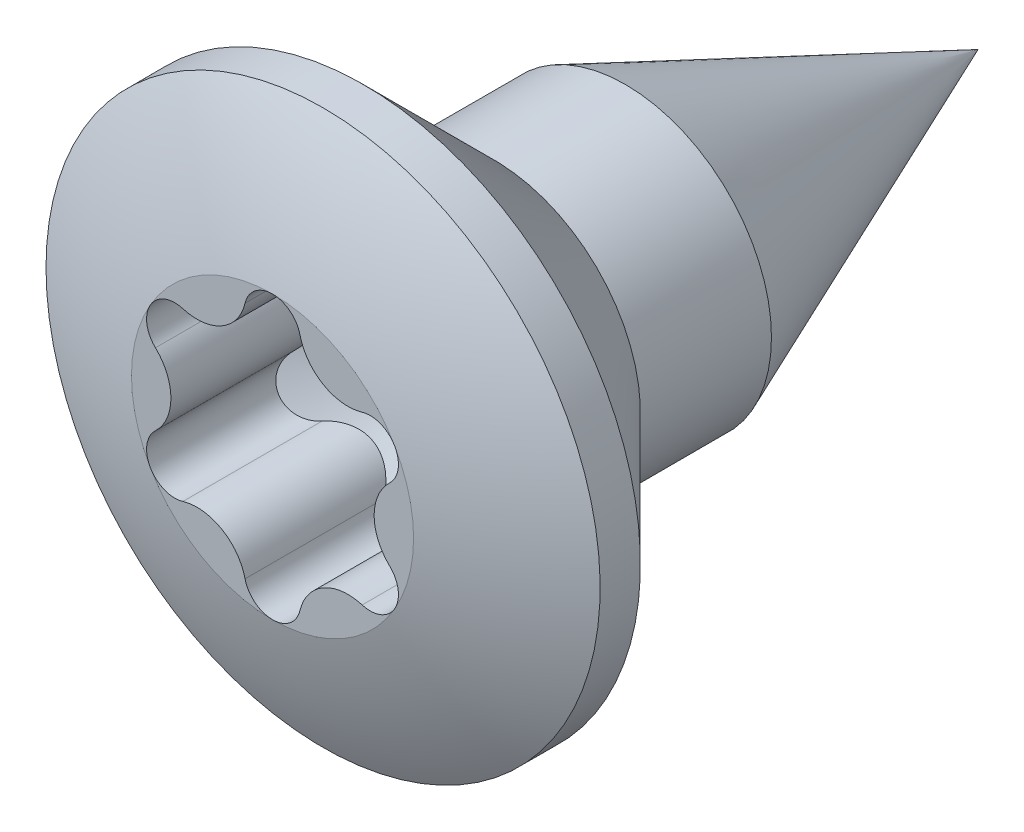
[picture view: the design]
ISO-10303-21;
HEADER;
FILE_DESCRIPTION(('STEP AP214'),'2;1');
FILE_NAME('part.step','',(''),(''),'','','');
FILE_SCHEMA(('AUTOMOTIVE_DESIGN { 1 0 10303 214 1 1 1 1 }'));
ENDSEC;
DATA;
#1=APPLICATION_CONTEXT('core data for automotive mechanical design processes');
#2=APPLICATION_PROTOCOL_DEFINITION('international standard','automotive_design',2000,#1);
#3=PRODUCT_CONTEXT('',#1,'mechanical');
#4=PRODUCT('Part','Part','',(#3));
#5=PRODUCT_RELATED_PRODUCT_CATEGORY('part','',(#4));
#6=PRODUCT_DEFINITION_FORMATION('','',#4);
#7=PRODUCT_DEFINITION_CONTEXT('part definition',#1,'design');
#8=PRODUCT_DEFINITION('design','',#6,#7);
#9=PRODUCT_DEFINITION_SHAPE('','',#8);
#10=(LENGTH_UNIT() NAMED_UNIT(*) SI_UNIT(.MILLI.,.METRE.));
#11=(NAMED_UNIT(*) PLANE_ANGLE_UNIT() SI_UNIT($,.RADIAN.));
#12=(NAMED_UNIT(*) SI_UNIT($,.STERADIAN.) SOLID_ANGLE_UNIT());
#13=UNCERTAINTY_MEASURE_WITH_UNIT(LENGTH_MEASURE(1.E-05),#10,'distance_accuracy_value','');
#14=(GEOMETRIC_REPRESENTATION_CONTEXT(3) GLOBAL_UNCERTAINTY_ASSIGNED_CONTEXT((#13)) GLOBAL_UNIT_ASSIGNED_CONTEXT((#10,
#11,#12)) REPRESENTATION_CONTEXT('',''));
#15=CARTESIAN_POINT('',(0.,0.,0.));
#16=DIRECTION('',(0.,0.,1.));
#17=DIRECTION('',(1.,0.,0.));
#18=AXIS2_PLACEMENT_3D('',#15,#16,#17);
#19=CARTESIAN_POINT('',(0.,0.,-2.1112048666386));
#20=DIRECTION('',(0.,0.,1.));
#21=DIRECTION('',(1.,0.,0.));
#22=AXIS2_PLACEMENT_3D('',#19,#20,#21);
#23=CONICAL_SURFACE('',#22,0.,1.02974425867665);
#24=CARTESIAN_POINT('',(0.,0.,-2.1112048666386));
#25=VERTEX_POINT('',#24);
#26=VERTEX_LOOP('',#25);
#27=FACE_BOUND('',#26,.T.);
#28=CARTESIAN_POINT('',(-0.889482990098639,0.828188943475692,-1.3809485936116));
#29=CARTESIAN_POINT('',(-0.905012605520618,0.832859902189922,-1.37220465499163));
#30=CARTESIAN_POINT('',(-0.921115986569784,0.836208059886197,-1.36371635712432));
#31=CARTESIAN_POINT('',(-0.954086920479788,0.840042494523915,-1.34741223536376));
#32=CARTESIAN_POINT('',(-0.970957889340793,0.840514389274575,-1.33959998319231));
#33=CARTESIAN_POINT('',(-1.00497300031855,0.838325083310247,-1.32487597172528));
#34=CARTESIAN_POINT('',(-1.02211786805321,0.835653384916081,-1.31796731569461));
#35=CARTESIAN_POINT('',(-1.05598176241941,0.827025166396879,-1.30531782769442));
#36=CARTESIAN_POINT('',(-1.07270160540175,0.821075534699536,-1.29957458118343));
#37=CARTESIAN_POINT('',(-1.1034719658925,0.806641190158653,-1.28995390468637));
#38=CARTESIAN_POINT('',(-1.11762414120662,0.798458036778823,-1.28594959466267));
#39=CARTESIAN_POINT('',(-1.14447104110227,0.779568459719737,-1.27921267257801));
#40=CARTESIAN_POINT('',(-1.15716729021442,0.768864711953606,-1.27647872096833));
#41=CARTESIAN_POINT('',(-1.17729540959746,0.748550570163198,-1.27296356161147));
#42=CARTESIAN_POINT('',(-1.18520819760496,0.739467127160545,-1.27185045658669));
#43=CARTESIAN_POINT('',(-1.1998230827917,0.720320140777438,-1.2703663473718));
#44=CARTESIAN_POINT('',(-1.2065255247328,0.710256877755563,-1.26999513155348));
#45=CARTESIAN_POINT('',(-1.21977835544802,0.687257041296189,-1.2700059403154));
#46=CARTESIAN_POINT('',(-1.22603166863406,0.674147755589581,-1.27055300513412));
#47=CARTESIAN_POINT('',(-1.23641852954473,0.647192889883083,-1.27271175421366));
#48=CARTESIAN_POINT('',(-1.24055077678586,0.633346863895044,-1.27432409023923));
#49=CARTESIAN_POINT('',(-1.24663514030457,0.605290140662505,-1.2785670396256));
#50=CARTESIAN_POINT('',(-1.24858010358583,0.591078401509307,-1.28120095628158));
#51=CARTESIAN_POINT('',(-1.25029508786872,0.562733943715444,-1.28740498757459));
#52=CARTESIAN_POINT('',(-1.25006510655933,0.54860122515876,-1.29097510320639));
#53=CARTESIAN_POINT('',(-1.24749330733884,0.520272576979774,-1.29909536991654));
#54=CARTESIAN_POINT('',(-1.24507670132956,0.506092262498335,-1.30367585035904));
#55=CARTESIAN_POINT('',(-1.23820796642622,0.478520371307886,-1.31361880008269));
#56=CARTESIAN_POINT('',(-1.23375477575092,0.465129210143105,-1.31898167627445));
#57=CARTESIAN_POINT('',(-1.22253305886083,0.438209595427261,-1.33089763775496));
#58=CARTESIAN_POINT('',(-1.2155883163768,0.424783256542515,-1.33751495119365));
#59=CARTESIAN_POINT('',(-1.19983715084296,0.399459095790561,-1.35138645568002));
#60=CARTESIAN_POINT('',(-1.191031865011,0.387560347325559,-1.35864025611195));
#61=CARTESIAN_POINT('',(-1.17525254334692,0.36936940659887,-1.3709921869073));
#62=CARTESIAN_POINT('',(-1.16873097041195,0.36258186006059,-1.37594624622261));
#63=CARTESIAN_POINT('',(-1.1619260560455,0.356175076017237,-1.380984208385));
#64=B_SPLINE_CURVE_WITH_KNOTS('',3,(#28,#29,#30,#31,#32,#33,#34,#35,#36,#37,#38,#39,#40,#41,#42,
#43,#44,#45,#46,#47,#48,#49,#50,#51,#52,#53,#54,#55,#56,#57,#58,#59,#60,#61,#62,#63),
.UNSPECIFIED.,.F.,.F.,(4,2,2,2,2,2,2,2,2,2,2,2,2,2,2,2,2,4),(0.,0.0552575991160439,
0.110791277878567,0.166510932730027,0.22211393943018,0.272328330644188,0.322489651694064,
0.358668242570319,0.394836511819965,0.438220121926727,0.481630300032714,0.525182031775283,
0.568733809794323,0.613833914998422,0.658957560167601,0.708259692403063,0.757531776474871,
0.789391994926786),.UNSPECIFIED.);
#65=CARTESIAN_POINT('',(-0.889682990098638,0.828248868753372,-1.38083610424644));
#66=VERTEX_POINT('',#65);
#67=CARTESIAN_POINT('',(-1.16212605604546,0.356363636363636,-1.38083610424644));
#68=VERTEX_POINT('',#67);
#69=EDGE_CURVE('E352',#66,#68,#64,.T.);
#70=ORIENTED_EDGE('',*,*,#69,.T.);
#71=CARTESIAN_POINT('',(-1.16232605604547,-0.356552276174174,-1.38068797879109));
#72=CARTESIAN_POINT('',(-1.14371471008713,-0.339008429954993,-1.3944473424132));
#73=CARTESIAN_POINT('',(-1.12623898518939,-0.319778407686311,-1.40780167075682));
#74=CARTESIAN_POINT('',(-1.0940425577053,-0.277971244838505,-1.43302652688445));
#75=CARTESIAN_POINT('',(-1.07934669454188,-0.25536688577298,-1.44488338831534));
#76=CARTESIAN_POINT('',(-1.05592099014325,-0.211603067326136,-1.46420788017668));
#77=CARTESIAN_POINT('',(-1.04659041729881,-0.19094971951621,-1.47208171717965));
#78=CARTESIAN_POINT('',(-1.03075231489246,-0.147964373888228,-1.48563194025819));
#79=CARTESIAN_POINT('',(-1.02423599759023,-0.125637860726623,-1.49131516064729));
#80=CARTESIAN_POINT('',(-1.01435941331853,-0.079551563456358,-1.49999377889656));
#81=CARTESIAN_POINT('',(-1.0110282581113,-0.0557806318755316,-1.50296437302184));
#82=CARTESIAN_POINT('',(-1.00791111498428,-0.007814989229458,-1.50574251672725));
#83=CARTESIAN_POINT('',(-1.00812457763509,0.0163796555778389,-1.50555055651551));
#84=CARTESIAN_POINT('',(-1.01181089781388,0.0610871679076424,-1.5022685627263));
#85=CARTESIAN_POINT('',(-1.01485301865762,0.0816670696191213,-1.49956155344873));
#86=CARTESIAN_POINT('',(-1.02339718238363,0.121903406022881,-1.49205082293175));
#87=CARTESIAN_POINT('',(-1.02889950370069,0.141559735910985,-1.48724686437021));
#88=CARTESIAN_POINT('',(-1.04242424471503,0.180555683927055,-1.4756266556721));
#89=CARTESIAN_POINT('',(-1.05056086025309,0.199828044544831,-1.46872028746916));
#90=CARTESIAN_POINT('',(-1.068925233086,0.236739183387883,-1.45343869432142));
#91=CARTESIAN_POINT('',(-1.0791555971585,0.254375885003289,-1.4450616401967));
#92=CARTESIAN_POINT('',(-1.1008414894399,0.287023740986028,-1.42768345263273));
#93=CARTESIAN_POINT('',(-1.1122089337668,0.302122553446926,-1.41873527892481));
#94=CARTESIAN_POINT('',(-1.13629839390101,0.330607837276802,-1.40016219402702));
#95=CARTESIAN_POINT('',(-1.14901444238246,0.344001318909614,-1.39054032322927));
#96=CARTESIAN_POINT('',(-1.16232605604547,0.356552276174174,-1.38068797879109));
#97=B_SPLINE_CURVE_WITH_KNOTS('',3,(#71,#72,#73,#74,#75,#76,#77,#78,#79,#80,#81,#82,#83,#84,#85,
#86,#87,#88,#89,#90,#91,#92,#93,#94,#95,#96),.UNSPECIFIED.,.F.,.F.,(4,2,2,2,2,2,2,2,2,2,2,2,4),
(0.,0.0872151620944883,0.175176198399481,0.246867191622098,0.318332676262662,0.390445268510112,
0.462546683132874,0.525200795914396,0.587862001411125,0.653718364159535,0.719657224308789,
0.782262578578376,0.844601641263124),.UNSPECIFIED.);
#98=CARTESIAN_POINT('',(-1.16212605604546,-0.356363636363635,-1.38083610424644));
#99=VERTEX_POINT('',#98);
#100=EDGE_CURVE('E272',#99,#68,#97,.T.);
#101=ORIENTED_EDGE('',*,*,#100,.F.);
#102=CARTESIAN_POINT('',(-1.16192605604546,-0.356175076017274,-1.38098420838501));
#103=CARTESIAN_POINT('',(-1.17373931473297,-0.367286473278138,-1.3722388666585));
#104=CARTESIAN_POINT('',(-1.18469402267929,-0.379556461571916,-1.36374908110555));
#105=CARTESIAN_POINT('',(-1.20450727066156,-0.406189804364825,-1.34744184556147));
#106=CARTESIAN_POINT('',(-1.21335506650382,-0.42056330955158,-1.33962796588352));
#107=CARTESIAN_POINT('',(-1.22847401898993,-0.451114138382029,-1.32490059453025));
#108=CARTESIAN_POINT('',(-1.23473645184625,-0.467297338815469,-1.31799020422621));
#109=CARTESIAN_POINT('',(-1.24420364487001,-0.500938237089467,-1.30533714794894));
#110=CARTESIAN_POINT('',(-1.24741476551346,-0.518393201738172,-1.2995920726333));
#111=CARTESIAN_POINT('',(-1.25030630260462,-0.552259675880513,-1.28996792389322));
#112=CARTESIAN_POINT('',(-1.25029873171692,-0.568608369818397,-1.28596196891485));
#113=CARTESIAN_POINT('',(-1.24736927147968,-0.601305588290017,-1.27922187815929));
#114=CARTESIAN_POINT('',(-1.2444505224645,-0.617654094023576,-1.27648637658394));
#115=CARTESIAN_POINT('',(-1.23694473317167,-0.645178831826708,-1.27297710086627));
#116=CARTESIAN_POINT('',(-1.23306322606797,-0.656509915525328,-1.27186728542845));
#117=CARTESIAN_POINT('',(-1.22386207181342,-0.678621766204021,-1.27038116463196));
#118=CARTESIAN_POINT('',(-1.21854281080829,-0.689402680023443,-1.27000466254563));
#119=CARTESIAN_POINT('',(-1.20528451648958,-0.712408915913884,-1.26999444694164));
#120=CARTESIAN_POINT('',(-1.19702890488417,-0.724453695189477,-1.27053576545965));
#121=CARTESIAN_POINT('',(-1.17880028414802,-0.747061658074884,-1.27269462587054));
#122=CARTESIAN_POINT('',(-1.16882619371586,-0.757623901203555,-1.27431284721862));
#123=CARTESIAN_POINT('',(-1.14751395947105,-0.776972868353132,-1.27856708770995));
#124=CARTESIAN_POINT('',(-1.13617862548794,-0.785763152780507,-1.28120103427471));
#125=CARTESIAN_POINT('',(-1.11248909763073,-0.801420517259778,-1.28740508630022));
#126=CARTESIAN_POINT('',(-1.10013492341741,-0.808287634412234,-1.29097517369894));
#127=CARTESIAN_POINT('',(-1.07431583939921,-0.820224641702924,-1.29909539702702));
#128=CARTESIAN_POINT('',(-1.06082705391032,-0.825221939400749,-1.30367586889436));
#129=CARTESIAN_POINT('',(-1.0335147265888,-0.833059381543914,-1.31361882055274));
#130=CARTESIAN_POINT('',(-1.01969101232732,-0.835898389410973,-1.3189817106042));
#131=CARTESIAN_POINT('',(-0.99076702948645,-0.839639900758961,-1.33089769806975));
#132=CARTESIAN_POINT('',(-0.975667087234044,-0.840338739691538,-1.337515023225));
#133=CARTESIAN_POINT('',(-0.94586012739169,-0.839359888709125,-1.35138653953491));
#134=CARTESIAN_POINT('',(-0.931152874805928,-0.837683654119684,-1.35864033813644));
#135=CARTESIAN_POINT('',(-0.907531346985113,-0.833118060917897,-1.37098080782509));
#136=CARTESIAN_POINT('',(-0.898413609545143,-0.830870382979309,-1.37592292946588));
#137=CARTESIAN_POINT('',(-0.889482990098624,-0.828188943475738,-1.38094859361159));
#138=B_SPLINE_CURVE_WITH_KNOTS('',3,(#102,#103,#104,#105,#106,#107,#108,#109,#110,#111,#112,
#113,#114,#115,#116,#117,#118,#119,#120,#121,#122,#123,#124,#125,#126,#127,#128,#129,#130,#131,
#132,#133,#134,#135,#136,#137),.UNSPECIFIED.,.F.,.F.,(4,2,2,2,2,2,2,2,2,2,2,2,2,2,2,2,2,4),(0.,
0.055261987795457,0.110800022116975,0.166523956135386,0.222131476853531,0.272349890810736,
0.322514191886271,0.358487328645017,0.394450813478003,0.438064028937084,0.481704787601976,
0.525256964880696,0.568808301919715,0.613908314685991,0.659032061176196,0.708334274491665,
0.757606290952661,0.789391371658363),.UNSPECIFIED.);
#139=CARTESIAN_POINT('',(-0.889682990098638,-0.828248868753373,-1.38083610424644));
#140=VERTEX_POINT('',#139);
#141=EDGE_CURVE('E252',#99,#140,#138,.T.);
#142=ORIENTED_EDGE('',*,*,#141,.T.);
#143=CARTESIAN_POINT('',(-0.27239567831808,-1.18481250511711,-1.38072536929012));
#144=CARTESIAN_POINT('',(-0.278286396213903,-1.15992581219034,-1.39448233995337));
#145=CARTESIAN_POINT('',(-0.286204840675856,-1.13517966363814,-1.4078341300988));
#146=CARTESIAN_POINT('',(-0.306317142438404,-1.08640000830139,-1.43305368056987));
#147=CARTESIAN_POINT('',(-0.318546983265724,-1.0623744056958,-1.44490777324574));
#148=CARTESIAN_POINT('',(-0.344737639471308,-1.02021115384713,-1.46422746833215));
#149=CARTESIAN_POINT('',(-0.357960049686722,-1.00180632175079,-1.47209923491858));
#150=CARTESIAN_POINT('',(-0.387269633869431,-0.966602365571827,-1.4856451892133));
#151=CARTESIAN_POINT('',(-0.403347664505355,-0.949798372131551,-1.49132621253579));
#152=CARTESIAN_POINT('',(-0.438322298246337,-0.918207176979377,-1.50000045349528));
#153=CARTESIAN_POINT('',(-0.457243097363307,-0.903439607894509,-1.50296887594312));
#154=CARTESIAN_POINT('',(-0.497223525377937,-0.876762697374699,-1.50574304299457));
#155=CARTESIAN_POINT('',(-0.518282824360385,-0.864852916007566,-1.50554927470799));
#156=CARTESIAN_POINT('',(-0.558843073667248,-0.845695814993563,-1.5022643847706));
#157=CARTESIAN_POINT('',(-0.578186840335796,-0.838042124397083,-1.49955608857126));
#158=CARTESIAN_POINT('',(-0.617304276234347,-0.825326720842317,-1.49204307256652));
#159=CARTESIAN_POINT('',(-0.637077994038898,-0.820265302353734,-1.48723811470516));
#160=CARTESIAN_POINT('',(-0.677612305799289,-0.81248293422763,-1.47561577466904));
#161=CARTESIAN_POINT('',(-0.698371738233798,-0.80989468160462,-1.46870816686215));
#162=CARTESIAN_POINT('',(-0.739521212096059,-0.807346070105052,-1.45342422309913));
#163=CARTESIAN_POINT('',(-0.759910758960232,-0.807389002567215,-1.44504606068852));
#164=CARTESIAN_POINT('',(-0.799009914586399,-0.809847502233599,-1.42767405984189));
#165=CARTESIAN_POINT('',(-0.817751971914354,-0.812140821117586,-1.41873411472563));
#166=CARTESIAN_POINT('',(-0.854431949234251,-0.818752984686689,-1.40017869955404));
#167=CARTESIAN_POINT('',(-0.872372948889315,-0.823063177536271,-1.39056626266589));
#168=CARTESIAN_POINT('',(-0.889882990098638,-0.828308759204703,-1.38072362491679));
#169=B_SPLINE_CURVE_WITH_KNOTS('',3,(#143,#144,#145,#146,#147,#148,#149,#150,#151,#152,#153,
#154,#155,#156,#157,#158,#159,#160,#161,#162,#163,#164,#165,#166,#167,#168),.UNSPECIFIED.,.F.,
.F.,(4,2,2,2,2,2,2,2,2,2,2,2,4),(0.,0.087205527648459,0.175156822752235,0.246842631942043,
0.318302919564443,0.39041005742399,0.462506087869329,0.525158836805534,0.587818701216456,
0.653677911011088,0.719619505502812,0.782166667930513,0.844447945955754),.UNSPECIFIED.);
#170=CARTESIAN_POINT('',(-0.27244306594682,-1.18461250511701,-1.38083610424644));
#171=VERTEX_POINT('',#170);
#172=EDGE_CURVE('E412',#171,#140,#169,.T.);
#173=ORIENTED_EDGE('',*,*,#172,.F.);
#174=CARTESIAN_POINT('',(-0.272490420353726,-1.18441250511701,-1.38094683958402));
#175=CARTESIAN_POINT('',(-0.268770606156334,-1.20019695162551,-1.37220296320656));
#176=CARTESIAN_POINT('',(-0.263618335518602,-1.21581687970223,-1.36371473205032));
#177=CARTESIAN_POINT('',(-0.250453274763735,-1.24628753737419,-1.34741076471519));
#178=CARTESIAN_POINT('',(-0.242426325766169,-1.26113403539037,-1.33959859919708));
#179=CARTESIAN_POINT('',(-0.223522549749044,-1.28949701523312,-1.32487477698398));
#180=CARTESIAN_POINT('',(-0.212636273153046,-1.30300887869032,-1.31796622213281));
#181=CARTESIAN_POINT('',(-0.188231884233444,-1.32802145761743,-1.30531690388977));
#182=CARTESIAN_POINT('',(-0.174719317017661,-1.33952631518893,-1.29957373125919));
#183=CARTESIAN_POINT('',(-0.146833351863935,-1.35895685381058,-1.28995316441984));
#184=CARTESIAN_POINT('',(-0.132670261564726,-1.36712133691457,-1.28594889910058));
#185=CARTESIAN_POINT('',(-0.102887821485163,-1.38092629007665,-1.27921215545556));
#186=CARTESIAN_POINT('',(-0.087270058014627,-1.38656947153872,-1.27647831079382));
#187=CARTESIAN_POINT('',(-0.059683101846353,-1.39382529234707,-1.27297212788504));
#188=CARTESIAN_POINT('',(-0.0479324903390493,-1.39612666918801,-1.27186360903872));
#189=CARTESIAN_POINT('',(-0.0241892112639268,-1.39920967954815,-1.27037965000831));
#190=CARTESIAN_POINT('',(-0.0121966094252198,-1.39999172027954,-1.27000401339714));
#191=CARTESIAN_POINT('',(0.0143530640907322,-1.4000098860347,-1.26999520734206));
#192=CARTESIAN_POINT('',(0.0289120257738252,-1.39888106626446,-1.2705373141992));
#193=CARTESIAN_POINT('',(0.0576052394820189,-1.39439532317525,-1.27269775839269));
#194=CARTESIAN_POINT('',(0.071739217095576,-1.39103699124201,-1.27431677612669));
#195=CARTESIAN_POINT('',(0.0991512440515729,-1.38225134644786,-1.27857258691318));
#196=CARTESIAN_POINT('',(0.112430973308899,-1.37682824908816,-1.28120730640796));
#197=CARTESIAN_POINT('',(0.137834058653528,-1.36413823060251,-1.28741286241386));
#198=CARTESIAN_POINT('',(0.149957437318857,-1.3568713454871,-1.29098368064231));
#199=CARTESIAN_POINT('',(0.173203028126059,-1.34047705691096,-1.29910538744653));
#200=CARTESIAN_POINT('',(0.184274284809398,-1.33129266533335,-1.30368662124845));
#201=CARTESIAN_POINT('',(0.204715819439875,-1.31155556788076,-1.31363105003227));
#202=CARTESIAN_POINT('',(0.214085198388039,-1.30100214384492,-1.31899465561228));
#203=CARTESIAN_POINT('',(0.231784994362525,-1.27782146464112,-1.33091215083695));
#204=CARTESIAN_POINT('',(0.239938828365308,-1.2650926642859,-1.33753027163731));
#205=CARTESIAN_POINT('',(0.253991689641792,-1.23878731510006,-1.3514033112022));
#206=CARTESIAN_POINT('',(0.259892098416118,-1.22521129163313,-1.35865783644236));
#207=CARTESIAN_POINT('',(0.267741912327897,-1.20248267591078,-1.37099262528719));
#208=CARTESIAN_POINT('',(0.27035012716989,-1.19347493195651,-1.37592807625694));
#209=CARTESIAN_POINT('',(0.272490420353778,-1.18441250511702,-1.38094683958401));
#210=B_SPLINE_CURVE_WITH_KNOTS('',3,(#174,#175,#176,#177,#178,#179,#180,#181,#182,#183,#184,
#185,#186,#187,#188,#189,#190,#191,#192,#193,#194,#195,#196,#197,#198,#199,#200,#201,#202,#203,
#204,#205,#206,#207,#208,#209),.UNSPECIFIED.,.F.,.F.,(4,2,2,2,2,2,2,2,2,2,2,2,2,2,2,2,2,4),(0.,
0.0552574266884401,0.110790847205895,0.166510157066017,0.222113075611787,0.272327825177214,
0.322488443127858,0.358450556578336,0.394403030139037,0.43801690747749,0.481658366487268,
0.525211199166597,0.568763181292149,0.613864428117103,0.658989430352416,0.708293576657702,
0.757567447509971,0.78930904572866),.UNSPECIFIED.);
#211=CARTESIAN_POINT('',(0.272443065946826,-1.18461250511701,-1.38083610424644));
#212=VERTEX_POINT('',#211);
#213=EDGE_CURVE('E448',#171,#212,#210,.T.);
#214=ORIENTED_EDGE('',*,*,#213,.T.);
#215=CARTESIAN_POINT('',(0.889882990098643,-0.828308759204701,-1.38072362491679));
#216=CARTESIAN_POINT('',(0.865385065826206,-0.820966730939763,-1.39448070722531));
#217=CARTESIAN_POINT('',(0.839994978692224,-0.815451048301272,-1.4078326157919));
#218=CARTESIAN_POINT('',(0.787694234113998,-0.808478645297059,-1.43305241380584));
#219=CARTESIAN_POINT('',(0.760772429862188,-0.807057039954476,-1.44490663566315));
#220=CARTESIAN_POINT('',(0.711162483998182,-0.808656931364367,-1.46422655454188));
#221=CARTESIAN_POINT('',(0.68861216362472,-0.810905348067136,-1.4720984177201));
#222=CARTESIAN_POINT('',(0.643469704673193,-0.81868600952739,-1.48564457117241));
#223=CARTESIAN_POINT('',(0.620877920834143,-0.82420790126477,-1.49132569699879));
#224=CARTESIAN_POINT('',(0.576031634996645,-0.838701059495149,-1.50000014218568));
#225=CARTESIAN_POINT('',(0.553782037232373,-0.847703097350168,-1.50296866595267));
#226=CARTESIAN_POINT('',(0.510688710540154,-0.868988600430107,-1.50574301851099));
#227=CARTESIAN_POINT('',(0.489844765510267,-0.881271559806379,-1.50554933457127));
#228=CARTESIAN_POINT('',(0.452973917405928,-0.906819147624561,-1.50226457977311));
#229=CARTESIAN_POINT('',(0.436673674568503,-0.919744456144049,-1.49955634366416));
#230=CARTESIAN_POINT('',(0.406102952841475,-0.947263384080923,-1.49204343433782));
#231=CARTESIAN_POINT('',(0.391832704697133,-0.961857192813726,-1.48723852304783));
#232=CARTESIAN_POINT('',(0.364825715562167,-0.993069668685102,-1.47561628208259));
#233=CARTESIAN_POINT('',(0.35220446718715,-1.00975367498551,-1.46870873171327));
#234=CARTESIAN_POINT('',(0.329422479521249,-1.04411573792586,-1.45342489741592));
#235=CARTESIAN_POINT('',(0.319264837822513,-1.06179501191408,-1.44504678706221));
#236=CARTESIAN_POINT('',(0.301844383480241,-1.09688480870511,-1.4276749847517));
#237=CARTESIAN_POINT('',(0.294459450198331,-1.11426230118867,-1.41873519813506));
#238=CARTESIAN_POINT('',(0.28184575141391,-1.14933364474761,-1.40018010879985));
#239=CARTESIAN_POINT('',(0.276607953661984,-1.16702583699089,-1.39056783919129));
#240=CARTESIAN_POINT('',(0.272395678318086,-1.18481250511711,-1.38072536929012));
#241=B_SPLINE_CURVE_WITH_KNOTS('',3,(#215,#216,#217,#218,#219,#220,#221,#222,#223,#224,#225,
#226,#227,#228,#229,#230,#231,#232,#233,#234,#235,#236,#237,#238,#239,#240),.UNSPECIFIED.,.F.,
.F.,(4,2,2,2,2,2,2,2,2,2,2,2,4),(0.,0.0872059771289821,0.175157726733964,0.246843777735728,
0.318304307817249,0.390411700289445,0.462507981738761,0.525160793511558,0.587820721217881,
0.653679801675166,0.719621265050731,0.782167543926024,0.844447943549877),.UNSPECIFIED.);
#242=CARTESIAN_POINT('',(0.889682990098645,-0.828248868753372,-1.38083610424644));
#243=VERTEX_POINT('',#242);
#244=EDGE_CURVE('E458',#243,#212,#241,.T.);
#245=ORIENTED_EDGE('',*,*,#244,.F.);
#246=CARTESIAN_POINT('',(0.889482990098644,-0.828188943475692,-1.3809485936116));
#247=CARTESIAN_POINT('',(0.905012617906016,-0.832859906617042,-1.3722046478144));
#248=CARTESIAN_POINT('',(0.9211160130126,-0.836208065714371,-1.36371634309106));
#249=CARTESIAN_POINT('',(0.954086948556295,-0.840042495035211,-1.34741222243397));
#250=CARTESIAN_POINT('',(0.97095790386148,-0.840514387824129,-1.33959997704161));
#251=CARTESIAN_POINT('',(1.00497295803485,-0.838325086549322,-1.32487598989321));
#252=CARTESIAN_POINT('',(1.02211778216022,-0.835653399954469,-1.3179673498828));
#253=CARTESIAN_POINT('',(1.05598168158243,-0.827025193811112,-1.30531785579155));
#254=CARTESIAN_POINT('',(1.07270157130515,-0.821075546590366,-1.29957459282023));
#255=CARTESIAN_POINT('',(1.10347212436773,-0.806641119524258,-1.28995385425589));
#256=CARTESIAN_POINT('',(1.11762443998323,-0.798457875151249,-1.2859495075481));
#257=CARTESIAN_POINT('',(1.14447134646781,-0.779568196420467,-1.2792126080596));
#258=CARTESIAN_POINT('',(1.15716749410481,-0.768864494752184,-1.27647868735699));
#259=CARTESIAN_POINT('',(1.17724157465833,-0.748604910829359,-1.27297296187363));
#260=CARTESIAN_POINT('',(1.18510709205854,-0.739583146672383,-1.27186469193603));
#261=CARTESIAN_POINT('',(1.19964404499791,-0.720570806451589,-1.27038063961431));
#262=CARTESIAN_POINT('',(1.20631579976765,-0.710580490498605,-1.27000466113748));
#263=CARTESIAN_POINT('',(1.21960641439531,-0.687602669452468,-1.26999444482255));
#264=CARTESIAN_POINT('',(1.22590969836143,-0.674430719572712,-1.27053575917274));
#265=CARTESIAN_POINT('',(1.23637447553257,-0.647340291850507,-1.27269461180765));
#266=CARTESIAN_POINT('',(1.24053460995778,-0.633421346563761,-1.27431283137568));
#267=CARTESIAN_POINT('',(1.24663520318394,-0.60528991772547,-1.27856706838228));
#268=CARTESIAN_POINT('',(1.24858015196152,-0.591078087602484,-1.28120101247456));
#269=CARTESIAN_POINT('',(1.25029507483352,-0.5627336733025,-1.28740505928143));
#270=CARTESIAN_POINT('',(1.25006509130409,-0.54860108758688,-1.29097514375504));
#271=CARTESIAN_POINT('',(1.24749331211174,-0.520272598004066,-1.29909536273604));
#272=CARTESIAN_POINT('',(1.24507671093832,-0.506092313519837,-1.30367583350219));
#273=CARTESIAN_POINT('',(1.2382079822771,-0.478520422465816,-1.31361878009));
#274=CARTESIAN_POINT('',(1.23375478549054,-0.465129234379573,-1.31898166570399));
#275=CARTESIAN_POINT('',(1.22253305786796,-0.438209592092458,-1.33089763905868));
#276=CARTESIAN_POINT('',(1.21558831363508,-0.424783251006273,-1.33751495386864));
#277=CARTESIAN_POINT('',(1.19983714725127,-0.399459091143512,-1.35138645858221));
#278=CARTESIAN_POINT('',(1.191031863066,-0.387560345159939,-1.35864025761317));
#279=CARTESIAN_POINT('',(1.17525254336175,-0.369369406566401,-1.37099218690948));
#280=CARTESIAN_POINT('',(1.16873097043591,-0.362581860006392,-1.37594624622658));
#281=CARTESIAN_POINT('',(1.1619260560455,-0.356175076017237,-1.380984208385));
#282=B_SPLINE_CURVE_WITH_KNOTS('',3,(#246,#247,#248,#249,#250,#251,#252,#253,#254,#255,#256,
#257,#258,#259,#260,#261,#262,#263,#264,#265,#266,#267,#268,#269,#270,#271,#272,#273,#274,#275,
#276,#277,#278,#279,#280,#281),.UNSPECIFIED.,.F.,.F.,(4,2,2,2,2,2,2,2,2,2,2,2,2,2,2,2,2,4),(0.,
0.055257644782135,0.11079127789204,0.166510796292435,0.222113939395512,0.272328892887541,
0.322489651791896,0.358437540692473,0.394375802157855,0.437988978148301,0.481629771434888,
0.525181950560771,0.568733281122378,0.613833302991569,0.658957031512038,0.708259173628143,
0.757531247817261,0.789391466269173),.UNSPECIFIED.);
#283=CARTESIAN_POINT('',(1.16212605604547,-0.356363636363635,-1.38083610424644));
#284=VERTEX_POINT('',#283);
#285=EDGE_CURVE('E477',#243,#284,#282,.T.);
#286=ORIENTED_EDGE('',*,*,#285,.T.);
#287=CARTESIAN_POINT('',(1.16232605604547,0.356552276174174,-1.38068797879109));
#288=CARTESIAN_POINT('',(1.14371471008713,0.339008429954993,-1.3944473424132));
#289=CARTESIAN_POINT('',(1.1262389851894,0.319778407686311,-1.40780167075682));
#290=CARTESIAN_POINT('',(1.0940425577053,0.277971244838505,-1.43302652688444));
#291=CARTESIAN_POINT('',(1.07934669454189,0.25536688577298,-1.44488338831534));
#292=CARTESIAN_POINT('',(1.05592099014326,0.211603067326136,-1.46420788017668));
#293=CARTESIAN_POINT('',(1.04659041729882,0.19094971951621,-1.47208171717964));
#294=CARTESIAN_POINT('',(1.03075231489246,0.147964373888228,-1.48563194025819));
#295=CARTESIAN_POINT('',(1.02423599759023,0.125637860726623,-1.49131516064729));
#296=CARTESIAN_POINT('',(1.01435941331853,0.079551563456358,-1.49999377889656));
#297=CARTESIAN_POINT('',(1.01102825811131,0.0557806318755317,-1.50296437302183));
#298=CARTESIAN_POINT('',(1.00791111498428,0.0078149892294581,-1.50574251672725));
#299=CARTESIAN_POINT('',(1.00812457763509,-0.0163796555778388,-1.50555055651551));
#300=CARTESIAN_POINT('',(1.01181089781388,-0.0610871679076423,-1.50226856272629));
#301=CARTESIAN_POINT('',(1.01485301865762,-0.0816670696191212,-1.49956155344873));
#302=CARTESIAN_POINT('',(1.02339718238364,-0.121903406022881,-1.49205082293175));
#303=CARTESIAN_POINT('',(1.02889950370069,-0.141559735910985,-1.4872468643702));
#304=CARTESIAN_POINT('',(1.04242424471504,-0.180555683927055,-1.4756266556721));
#305=CARTESIAN_POINT('',(1.05056086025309,-0.199828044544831,-1.46872028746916));
#306=CARTESIAN_POINT('',(1.068925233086,-0.236739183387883,-1.45343869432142));
#307=CARTESIAN_POINT('',(1.0791555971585,-0.254375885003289,-1.4450616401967));
#308=CARTESIAN_POINT('',(1.1008414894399,-0.287023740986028,-1.42768345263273));
#309=CARTESIAN_POINT('',(1.1122089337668,-0.302122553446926,-1.41873527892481));
#310=CARTESIAN_POINT('',(1.13629839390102,-0.330607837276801,-1.40016219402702));
#311=CARTESIAN_POINT('',(1.14901444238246,-0.344001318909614,-1.39054032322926));
#312=CARTESIAN_POINT('',(1.16232605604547,-0.356552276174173,-1.38068797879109));
#313=B_SPLINE_CURVE_WITH_KNOTS('',3,(#287,#288,#289,#290,#291,#292,#293,#294,#295,#296,#297,
#298,#299,#300,#301,#302,#303,#304,#305,#306,#307,#308,#309,#310,#311,#312),.UNSPECIFIED.,.F.,
.F.,(4,2,2,2,2,2,2,2,2,2,2,2,4),(0.,0.087215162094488,0.175176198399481,0.246867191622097,
0.318332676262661,0.390445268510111,0.462546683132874,0.525200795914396,0.587862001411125,
0.653718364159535,0.719657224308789,0.782262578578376,0.844601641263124),.UNSPECIFIED.);
#314=CARTESIAN_POINT('',(1.16212605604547,0.35636363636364,-1.38083610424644));
#315=VERTEX_POINT('',#314);
#316=EDGE_CURVE('E488',#315,#284,#313,.T.);
#317=ORIENTED_EDGE('',*,*,#316,.F.);
#318=CARTESIAN_POINT('',(1.16192605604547,0.356175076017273,-1.38098420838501));
#319=CARTESIAN_POINT('',(1.17373931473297,0.367286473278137,-1.3722388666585));
#320=CARTESIAN_POINT('',(1.18469402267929,0.379556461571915,-1.36374908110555));
#321=CARTESIAN_POINT('',(1.20450727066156,0.406189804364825,-1.34744184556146));
#322=CARTESIAN_POINT('',(1.21335506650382,0.420563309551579,-1.33962796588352));
#323=CARTESIAN_POINT('',(1.22847401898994,0.451114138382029,-1.32490059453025));
#324=CARTESIAN_POINT('',(1.23473645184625,0.467297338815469,-1.31799020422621));
#325=CARTESIAN_POINT('',(1.24420364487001,0.500938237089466,-1.30533714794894));
#326=CARTESIAN_POINT('',(1.24741476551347,0.518393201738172,-1.2995920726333));
#327=CARTESIAN_POINT('',(1.25030630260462,0.552259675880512,-1.28996792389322));
#328=CARTESIAN_POINT('',(1.25029873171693,0.568608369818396,-1.28596196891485));
#329=CARTESIAN_POINT('',(1.24736927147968,0.601305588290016,-1.27922187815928));
#330=CARTESIAN_POINT('',(1.24445052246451,0.617654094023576,-1.27648637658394));
#331=CARTESIAN_POINT('',(1.23694473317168,0.645178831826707,-1.27297710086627));
#332=CARTESIAN_POINT('',(1.23306322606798,0.656509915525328,-1.27186728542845));
#333=CARTESIAN_POINT('',(1.22386207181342,0.678621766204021,-1.27038116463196));
#334=CARTESIAN_POINT('',(1.2185428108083,0.689402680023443,-1.27000466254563));
#335=CARTESIAN_POINT('',(1.20528451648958,0.712408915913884,-1.26999444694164));
#336=CARTESIAN_POINT('',(1.19702890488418,0.724453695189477,-1.27053576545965));
#337=CARTESIAN_POINT('',(1.17880028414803,0.747061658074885,-1.27269462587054));
#338=CARTESIAN_POINT('',(1.16882619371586,0.757623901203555,-1.27431284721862));
#339=CARTESIAN_POINT('',(1.14751395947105,0.776972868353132,-1.27856708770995));
#340=CARTESIAN_POINT('',(1.13617862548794,0.785763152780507,-1.28120103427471));
#341=CARTESIAN_POINT('',(1.11248909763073,0.801420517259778,-1.28740508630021));
#342=CARTESIAN_POINT('',(1.10013492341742,0.808287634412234,-1.29097517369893));
#343=CARTESIAN_POINT('',(1.07431583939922,0.820224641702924,-1.29909539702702));
#344=CARTESIAN_POINT('',(1.06082705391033,0.825221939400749,-1.30367586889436));
#345=CARTESIAN_POINT('',(1.0335147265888,0.833059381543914,-1.31361882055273));
#346=CARTESIAN_POINT('',(1.01969101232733,0.835898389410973,-1.3189817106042));
#347=CARTESIAN_POINT('',(0.990767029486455,0.839639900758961,-1.33089769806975));
#348=CARTESIAN_POINT('',(0.975667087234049,0.840338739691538,-1.337515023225));
#349=CARTESIAN_POINT('',(0.945860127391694,0.839359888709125,-1.35138653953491));
#350=CARTESIAN_POINT('',(0.931152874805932,0.837683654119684,-1.35864033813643));
#351=CARTESIAN_POINT('',(0.907531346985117,0.833118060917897,-1.37098080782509));
#352=CARTESIAN_POINT('',(0.898413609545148,0.830870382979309,-1.37592292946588));
#353=CARTESIAN_POINT('',(0.889482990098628,0.828188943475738,-1.38094859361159));
#354=B_SPLINE_CURVE_WITH_KNOTS('',3,(#318,#319,#320,#321,#322,#323,#324,#325,#326,#327,#328,
#329,#330,#331,#332,#333,#334,#335,#336,#337,#338,#339,#340,#341,#342,#343,#344,#345,#346,#347,
#348,#349,#350,#351,#352,#353),.UNSPECIFIED.,.F.,.F.,(4,2,2,2,2,2,2,2,2,2,2,2,2,2,2,2,2,4),(0.,
0.0552619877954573,0.110800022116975,0.166523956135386,0.222131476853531,0.272349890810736,
0.322514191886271,0.358487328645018,0.394450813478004,0.438064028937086,0.481704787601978,
0.525256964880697,0.568808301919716,0.613908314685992,0.659032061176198,0.708334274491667,
0.757606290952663,0.789391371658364),.UNSPECIFIED.);
#355=CARTESIAN_POINT('',(0.889682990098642,0.828248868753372,-1.38083610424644));
#356=VERTEX_POINT('',#355);
#357=EDGE_CURVE('E361',#315,#356,#354,.T.);
#358=ORIENTED_EDGE('',*,*,#357,.T.);
#359=CARTESIAN_POINT('',(0.272395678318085,1.18481250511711,-1.38072536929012));
#360=CARTESIAN_POINT('',(0.278286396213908,1.15992581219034,-1.39448233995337));
#361=CARTESIAN_POINT('',(0.286204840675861,1.13517966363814,-1.4078341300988));
#362=CARTESIAN_POINT('',(0.306317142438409,1.08640000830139,-1.43305368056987));
#363=CARTESIAN_POINT('',(0.318546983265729,1.0623744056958,-1.44490777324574));
#364=CARTESIAN_POINT('',(0.344737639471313,1.02021115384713,-1.46422746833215));
#365=CARTESIAN_POINT('',(0.357960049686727,1.00180632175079,-1.47209923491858));
#366=CARTESIAN_POINT('',(0.387269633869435,0.966602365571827,-1.4856451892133));
#367=CARTESIAN_POINT('',(0.40334766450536,0.949798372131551,-1.49132621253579));
#368=CARTESIAN_POINT('',(0.438322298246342,0.918207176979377,-1.50000045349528));
#369=CARTESIAN_POINT('',(0.457243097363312,0.903439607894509,-1.50296887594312));
#370=CARTESIAN_POINT('',(0.497223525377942,0.876762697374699,-1.50574304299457));
#371=CARTESIAN_POINT('',(0.51828282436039,0.864852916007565,-1.50554927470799));
#372=CARTESIAN_POINT('',(0.558843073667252,0.845695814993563,-1.50226438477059));
#373=CARTESIAN_POINT('',(0.578186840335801,0.838042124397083,-1.49955608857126));
#374=CARTESIAN_POINT('',(0.617304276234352,0.825326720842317,-1.49204307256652));
#375=CARTESIAN_POINT('',(0.637077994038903,0.820265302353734,-1.48723811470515));
#376=CARTESIAN_POINT('',(0.677612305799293,0.812482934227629,-1.47561577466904));
#377=CARTESIAN_POINT('',(0.698371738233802,0.80989468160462,-1.46870816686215));
#378=CARTESIAN_POINT('',(0.739521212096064,0.807346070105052,-1.45342422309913));
#379=CARTESIAN_POINT('',(0.759910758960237,0.807389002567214,-1.44504606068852));
#380=CARTESIAN_POINT('',(0.799009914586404,0.809847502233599,-1.42767405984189));
#381=CARTESIAN_POINT('',(0.817751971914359,0.812140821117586,-1.41873411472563));
#382=CARTESIAN_POINT('',(0.854431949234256,0.818752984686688,-1.40017869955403));
#383=CARTESIAN_POINT('',(0.872372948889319,0.82306317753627,-1.39056626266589));
#384=CARTESIAN_POINT('',(0.889882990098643,0.828308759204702,-1.38072362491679));
#385=B_SPLINE_CURVE_WITH_KNOTS('',3,(#359,#360,#361,#362,#363,#364,#365,#366,#367,#368,#369,
#370,#371,#372,#373,#374,#375,#376,#377,#378,#379,#380,#381,#382,#383,#384),.UNSPECIFIED.,.F.,
.F.,(4,2,2,2,2,2,2,2,2,2,2,2,4),(0.,0.0872055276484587,0.175156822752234,0.246842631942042,
0.318302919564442,0.39041005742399,0.462506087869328,0.525158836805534,0.587818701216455,
0.653677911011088,0.719619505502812,0.782166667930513,0.844447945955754),.UNSPECIFIED.);
#386=CARTESIAN_POINT('',(0.272443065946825,1.18461250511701,-1.38083610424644));
#387=VERTEX_POINT('',#386);
#388=EDGE_CURVE('E386',#387,#356,#385,.T.);
#389=ORIENTED_EDGE('',*,*,#388,.F.);
#390=CARTESIAN_POINT('',(0.272490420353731,1.18441250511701,-1.38094683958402));
#391=CARTESIAN_POINT('',(0.268770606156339,1.20019695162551,-1.37220296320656));
#392=CARTESIAN_POINT('',(0.263618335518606,1.21581687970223,-1.36371473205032));
#393=CARTESIAN_POINT('',(0.25045327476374,1.24628753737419,-1.34741076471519));
#394=CARTESIAN_POINT('',(0.242426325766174,1.26113403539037,-1.33959859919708));
#395=CARTESIAN_POINT('',(0.223522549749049,1.28949701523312,-1.32487477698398));
#396=CARTESIAN_POINT('',(0.212636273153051,1.30300887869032,-1.31796622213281));
#397=CARTESIAN_POINT('',(0.188231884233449,1.32802145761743,-1.30531690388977));
#398=CARTESIAN_POINT('',(0.174719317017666,1.33952631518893,-1.29957373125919));
#399=CARTESIAN_POINT('',(0.14683335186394,1.35895685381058,-1.28995316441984));
#400=CARTESIAN_POINT('',(0.132670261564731,1.36712133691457,-1.28594889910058));
#401=CARTESIAN_POINT('',(0.102887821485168,1.38092629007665,-1.27921215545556));
#402=CARTESIAN_POINT('',(0.0872700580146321,1.38656947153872,-1.27647831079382));
#403=CARTESIAN_POINT('',(0.0596831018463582,1.39382529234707,-1.27297212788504));
#404=CARTESIAN_POINT('',(0.0479324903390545,1.39612666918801,-1.27186360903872));
#405=CARTESIAN_POINT('',(0.0241892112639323,1.39920967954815,-1.27037965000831));
#406=CARTESIAN_POINT('',(0.0121966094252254,1.39999172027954,-1.27000401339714));
#407=CARTESIAN_POINT('',(-0.0143530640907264,1.4000098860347,-1.26999520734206));
#408=CARTESIAN_POINT('',(-0.0289120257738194,1.39888106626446,-1.2705373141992));
#409=CARTESIAN_POINT('',(-0.0576052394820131,1.39439532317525,-1.27269775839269));
#410=CARTESIAN_POINT('',(-0.0717392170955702,1.39103699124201,-1.27431677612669));
#411=CARTESIAN_POINT('',(-0.099151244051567,1.38225134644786,-1.27857258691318));
#412=CARTESIAN_POINT('',(-0.112430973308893,1.37682824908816,-1.28120730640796));
#413=CARTESIAN_POINT('',(-0.137834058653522,1.36413823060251,-1.28741286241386));
#414=CARTESIAN_POINT('',(-0.149957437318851,1.3568713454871,-1.29098368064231));
#415=CARTESIAN_POINT('',(-0.173203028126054,1.34047705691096,-1.29910538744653));
#416=CARTESIAN_POINT('',(-0.184274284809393,1.33129266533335,-1.30368662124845));
#417=CARTESIAN_POINT('',(-0.204715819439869,1.31155556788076,-1.31363105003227));
#418=CARTESIAN_POINT('',(-0.214085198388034,1.30100214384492,-1.31899465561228));
#419=CARTESIAN_POINT('',(-0.231784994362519,1.27782146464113,-1.33091215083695));
#420=CARTESIAN_POINT('',(-0.239938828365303,1.2650926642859,-1.33753027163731));
#421=CARTESIAN_POINT('',(-0.253991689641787,1.23878731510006,-1.3514033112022));
#422=CARTESIAN_POINT('',(-0.259892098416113,1.22521129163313,-1.35865783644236));
#423=CARTESIAN_POINT('',(-0.267741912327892,1.20248267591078,-1.37099262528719));
#424=CARTESIAN_POINT('',(-0.270350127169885,1.19347493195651,-1.37592807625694));
#425=CARTESIAN_POINT('',(-0.272490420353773,1.18441250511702,-1.38094683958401));
#426=B_SPLINE_CURVE_WITH_KNOTS('',3,(#390,#391,#392,#393,#394,#395,#396,#397,#398,#399,#400,
#401,#402,#403,#404,#405,#406,#407,#408,#409,#410,#411,#412,#413,#414,#415,#416,#417,#418,#419,
#420,#421,#422,#423,#424,#425),.UNSPECIFIED.,.F.,.F.,(4,2,2,2,2,2,2,2,2,2,2,2,2,2,2,2,2,4),(0.,
0.0552574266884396,0.110790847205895,0.166510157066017,0.222113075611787,0.272327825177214,
0.322488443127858,0.358450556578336,0.394403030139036,0.438016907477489,0.481658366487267,
0.525211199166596,0.568763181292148,0.613864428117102,0.658989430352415,0.7082935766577,
0.75756744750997,0.789309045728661),.UNSPECIFIED.);
#427=CARTESIAN_POINT('',(-0.272443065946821,1.18461250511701,-1.38083610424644));
#428=VERTEX_POINT('',#427);
#429=EDGE_CURVE('E346',#387,#428,#426,.T.);
#430=ORIENTED_EDGE('',*,*,#429,.T.);
#431=CARTESIAN_POINT('',(-0.889882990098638,0.828308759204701,-1.38072362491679));
#432=CARTESIAN_POINT('',(-0.865385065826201,0.820966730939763,-1.39448070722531));
#433=CARTESIAN_POINT('',(-0.83999497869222,0.815451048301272,-1.4078326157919));
#434=CARTESIAN_POINT('',(-0.787694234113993,0.808478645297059,-1.43305241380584));
#435=CARTESIAN_POINT('',(-0.760772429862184,0.807057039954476,-1.44490663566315));
#436=CARTESIAN_POINT('',(-0.711162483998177,0.808656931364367,-1.46422655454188));
#437=CARTESIAN_POINT('',(-0.688612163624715,0.810905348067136,-1.4720984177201));
#438=CARTESIAN_POINT('',(-0.643469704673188,0.81868600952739,-1.48564457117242));
#439=CARTESIAN_POINT('',(-0.620877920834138,0.82420790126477,-1.49132569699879));
#440=CARTESIAN_POINT('',(-0.576031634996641,0.838701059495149,-1.50000014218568));
#441=CARTESIAN_POINT('',(-0.553782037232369,0.847703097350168,-1.50296866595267));
#442=CARTESIAN_POINT('',(-0.51068871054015,0.868988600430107,-1.50574301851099));
#443=CARTESIAN_POINT('',(-0.489844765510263,0.881271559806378,-1.50554933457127));
#444=CARTESIAN_POINT('',(-0.452973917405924,0.906819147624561,-1.50226457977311));
#445=CARTESIAN_POINT('',(-0.436673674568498,0.919744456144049,-1.49955634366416));
#446=CARTESIAN_POINT('',(-0.406102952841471,0.947263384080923,-1.49204343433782));
#447=CARTESIAN_POINT('',(-0.391832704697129,0.961857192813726,-1.48723852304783));
#448=CARTESIAN_POINT('',(-0.364825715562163,0.993069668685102,-1.47561628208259));
#449=CARTESIAN_POINT('',(-0.352204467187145,1.00975367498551,-1.46870873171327));
#450=CARTESIAN_POINT('',(-0.329422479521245,1.04411573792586,-1.45342489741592));
#451=CARTESIAN_POINT('',(-0.319264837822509,1.06179501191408,-1.44504678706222));
#452=CARTESIAN_POINT('',(-0.301844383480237,1.09688480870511,-1.4276749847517));
#453=CARTESIAN_POINT('',(-0.294459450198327,1.11426230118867,-1.41873519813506));
#454=CARTESIAN_POINT('',(-0.281845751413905,1.14933364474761,-1.40018010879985));
#455=CARTESIAN_POINT('',(-0.276607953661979,1.16702583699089,-1.39056783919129));
#456=CARTESIAN_POINT('',(-0.272395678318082,1.18481250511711,-1.38072536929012));
#457=B_SPLINE_CURVE_WITH_KNOTS('',3,(#431,#432,#433,#434,#435,#436,#437,#438,#439,#440,#441,
#442,#443,#444,#445,#446,#447,#448,#449,#450,#451,#452,#453,#454,#455,#456),.UNSPECIFIED.,.F.,
.F.,(4,2,2,2,2,2,2,2,2,2,2,2,4),(0.,0.0872059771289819,0.175157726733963,0.246843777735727,
0.318304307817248,0.390411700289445,0.46250798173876,0.525160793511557,0.58782072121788,
0.653679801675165,0.71962126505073,0.782167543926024,0.844447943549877),.UNSPECIFIED.);
#458=EDGE_CURVE('E156',#66,#428,#457,.T.);
#459=ORIENTED_EDGE('',*,*,#458,.F.);
#460=EDGE_LOOP('',(#70,#101,#142,#173,#214,#245,#286,#317,#358,#389,#430,#459));
#461=FACE_BOUND('',#460,.T.);
#462=ADVANCED_FACE('F133',(#27,#461),#23,.F.);
#463=CARTESIAN_POINT('',(0.,0.,-5.83438085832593));
#464=DIRECTION('',(0.,0.,-1.));
#465=DIRECTION('',(0.,1.,0.));
#466=AXIS2_PLACEMENT_3D('',#463,#464,#465);
#467=SPHERICAL_SURFACE('',#466,6.);
#468=CARTESIAN_POINT('',(0.,0.,0.));
#469=DIRECTION('',(0.,0.,-1.));
#470=DIRECTION('',(-1.,0.,0.));
#471=AXIS2_PLACEMENT_3D('',#468,#469,#470);
#472=CIRCLE('',#471,1.4);
#473=CARTESIAN_POINT('',(-1.21243556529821,0.7,0.));
#474=VERTEX_POINT('',#473);
#475=CARTESIAN_POINT('',(0.,1.4,0.));
#476=VERTEX_POINT('',#475);
#477=EDGE_CURVE('E343',#474,#476,#472,.T.);
#478=ORIENTED_EDGE('',*,*,#477,.T.);
#479=CARTESIAN_POINT('',(0.,0.,0.));
#480=DIRECTION('',(0.,0.,1.));
#481=DIRECTION('',(1.,0.,0.));
#482=AXIS2_PLACEMENT_3D('',#479,#480,#481);
#483=CIRCLE('',#482,1.4);
#484=CARTESIAN_POINT('',(1.21243556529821,0.7,0.));
#485=VERTEX_POINT('',#484);
#486=EDGE_CURVE('E148',#485,#476,#483,.T.);
#487=ORIENTED_EDGE('',*,*,#486,.F.);
#488=CARTESIAN_POINT('',(0.,0.,0.));
#489=DIRECTION('',(0.,0.,1.));
#490=DIRECTION('',(1.,0.,0.));
#491=AXIS2_PLACEMENT_3D('',#488,#489,#490);
#492=CIRCLE('',#491,1.4);
#493=CARTESIAN_POINT('',(1.21243556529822,-0.699999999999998,0.));
#494=VERTEX_POINT('',#493);
#495=EDGE_CURVE('E456',#494,#485,#492,.T.);
#496=ORIENTED_EDGE('',*,*,#495,.F.);
#497=CARTESIAN_POINT('',(0.,0.,0.));
#498=DIRECTION('',(0.,0.,1.));
#499=DIRECTION('',(1.,0.,0.));
#500=AXIS2_PLACEMENT_3D('',#497,#498,#499);
#501=CIRCLE('',#500,1.4);
#502=CARTESIAN_POINT('',(0.,-1.4,0.));
#503=VERTEX_POINT('',#502);
#504=EDGE_CURVE('E413',#503,#494,#501,.T.);
#505=ORIENTED_EDGE('',*,*,#504,.F.);
#506=CARTESIAN_POINT('',(0.,0.,0.));
#507=DIRECTION('',(0.,0.,1.));
#508=DIRECTION('',(1.,0.,0.));
#509=AXIS2_PLACEMENT_3D('',#506,#507,#508);
#510=CIRCLE('',#509,1.4);
#511=CARTESIAN_POINT('',(-1.21243556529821,-0.7,0.));
#512=VERTEX_POINT('',#511);
#513=EDGE_CURVE('E265',#512,#503,#510,.T.);
#514=ORIENTED_EDGE('',*,*,#513,.F.);
#515=CARTESIAN_POINT('',(0.,0.,0.));
#516=DIRECTION('',(0.,0.,1.));
#517=DIRECTION('',(1.,0.,0.));
#518=AXIS2_PLACEMENT_3D('',#515,#516,#517);
#519=CIRCLE('',#518,1.4);
#520=EDGE_CURVE('E264',#474,#512,#519,.T.);
#521=ORIENTED_EDGE('',*,*,#520,.F.);
#522=EDGE_LOOP('',(#478,#487,#496,#505,#514,#521));
#523=FACE_BOUND('',#522,.T.);
#524=CARTESIAN_POINT('',(0.,0.,-0.501698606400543));
#525=DIRECTION('',(0.,0.,-1.));
#526=DIRECTION('',(-1.,0.,0.));
#527=AXIS2_PLACEMENT_3D('',#524,#525,#526);
#528=CIRCLE('',#527,2.75);
#529=CARTESIAN_POINT('',(-2.75,0.,-0.501698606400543));
#530=VERTEX_POINT('',#529);
#531=EDGE_CURVE('E12',#530,#530,#528,.T.);
#532=ORIENTED_EDGE('',*,*,#531,.F.);
#533=EDGE_LOOP('',(#532));
#534=FACE_BOUND('',#533,.T.);
#535=ADVANCED_FACE('F135',(#523,#534),#467,.T.);
#536=CARTESIAN_POINT('',(0.,0.,0.));
#537=DIRECTION('',(0.,0.,-1.));
#538=DIRECTION('',(-1.,0.,0.));
#539=AXIS2_PLACEMENT_3D('',#536,#537,#538);
#540=CYLINDRICAL_SURFACE('',#539,2.75);
#541=ORIENTED_EDGE('',*,*,#531,.T.);
#542=EDGE_LOOP('',(#541));
#543=FACE_BOUND('',#542,.T.);
#544=CARTESIAN_POINT('',(0.,0.,-0.901698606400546));
#545=DIRECTION('',(0.,0.,-1.));
#546=DIRECTION('',(-1.,0.,0.));
#547=AXIS2_PLACEMENT_3D('',#544,#545,#546);
#548=CIRCLE('',#547,2.75);
#549=CARTESIAN_POINT('',(-2.75,0.,-0.901698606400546));
#550=VERTEX_POINT('',#549);
#551=EDGE_CURVE('E141',#550,#550,#548,.T.);
#552=ORIENTED_EDGE('',*,*,#551,.F.);
#553=EDGE_LOOP('',(#552));
#554=FACE_BOUND('',#553,.T.);
#555=ADVANCED_FACE('F302',(#543,#554),#540,.T.);
#556=CARTESIAN_POINT('',(0.,0.,-2.20169860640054));
#557=DIRECTION('',(0.,0.,1.));
#558=DIRECTION('',(1.,0.,0.));
#559=AXIS2_PLACEMENT_3D('',#556,#557,#558);
#560=CONICAL_SURFACE('',#559,1.45,0.78539816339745);
#561=ORIENTED_EDGE('',*,*,#551,.T.);
#562=EDGE_LOOP('',(#561));
#563=FACE_BOUND('',#562,.T.);
#564=CARTESIAN_POINT('',(0.,0.,-2.20169860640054));
#565=DIRECTION('',(0.,0.,-1.));
#566=DIRECTION('',(-1.,0.,0.));
#567=AXIS2_PLACEMENT_3D('',#564,#565,#566);
#568=CIRCLE('',#567,1.45);
#569=CARTESIAN_POINT('',(-1.45,0.,-2.20169860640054));
#570=VERTEX_POINT('',#569);
#571=EDGE_CURVE('E333',#570,#570,#568,.T.);
#572=ORIENTED_EDGE('',*,*,#571,.F.);
#573=EDGE_LOOP('',(#572));
#574=FACE_BOUND('',#573,.T.);
#575=ADVANCED_FACE('F321',(#563,#574),#560,.T.);
#576=CARTESIAN_POINT('',(0.,0.,0.));
#577=DIRECTION('',(0.,0.,-1.));
#578=DIRECTION('',(-1.,0.,0.));
#579=AXIS2_PLACEMENT_3D('',#576,#577,#578);
#580=CYLINDRICAL_SURFACE('',#579,1.45);
#581=ORIENTED_EDGE('',*,*,#571,.T.);
#582=EDGE_LOOP('',(#581));
#583=FACE_BOUND('',#582,.T.);
#584=CARTESIAN_POINT('',(0.,0.,-3.50229604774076));
#585=DIRECTION('',(0.,0.,-1.));
#586=DIRECTION('',(-1.,0.,0.));
#587=AXIS2_PLACEMENT_3D('',#584,#585,#586);
#588=CIRCLE('',#587,1.45);
#589=CARTESIAN_POINT('',(1.45,0.,-3.50229604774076));
#590=VERTEX_POINT('',#589);
#591=EDGE_CURVE('E335',#590,#590,#588,.T.);
#592=ORIENTED_EDGE('',*,*,#591,.F.);
#593=EDGE_LOOP('',(#592));
#594=FACE_BOUND('',#593,.T.);
#595=ADVANCED_FACE('F317',(#583,#594),#580,.T.);
#596=CARTESIAN_POINT('',(0.,0.,-7.00169860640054));
#597=DIRECTION('',(0.,0.,1.));
#598=DIRECTION('',(1.,0.,0.));
#599=AXIS2_PLACEMENT_3D('',#596,#597,#598);
#600=CONICAL_SURFACE('',#599,0.000500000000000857,0.392699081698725);
#601=CARTESIAN_POINT('',(0.,0.,-7.00169860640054));
#602=DIRECTION('',(0.,0.,-1.));
#603=DIRECTION('',(-1.,0.,0.));
#604=AXIS2_PLACEMENT_3D('',#601,#602,#603);
#605=CIRCLE('',#604,0.000500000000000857);
#606=CARTESIAN_POINT('',(0.000500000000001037,0.,-7.00169860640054));
#607=VERTEX_POINT('',#606);
#608=EDGE_CURVE('E340',#607,#607,#605,.T.);
#609=CARTESIAN_POINT('',(1.45,0.,-3.50229604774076));
#610=CARTESIAN_POINT('',(1.43490104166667,0.,-3.5387481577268));
#611=CARTESIAN_POINT('',(1.41980208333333,0.,-3.57520026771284));
#612=CARTESIAN_POINT('',(1.38960416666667,0.,-3.64810448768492));
#613=CARTESIAN_POINT('',(1.37450520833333,0.,-3.68455659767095));
#614=CARTESIAN_POINT('',(1.34430729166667,0.,-3.75746081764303));
#615=CARTESIAN_POINT('',(1.32920833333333,0.,-3.79391292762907));
#616=CARTESIAN_POINT('',(1.29901041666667,0.,-3.86681714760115));
#617=CARTESIAN_POINT('',(1.28391145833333,0.,-3.90326925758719));
#618=CARTESIAN_POINT('',(1.25371354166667,0.,-3.97617347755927));
#619=CARTESIAN_POINT('',(1.23861458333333,0.,-4.01262558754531));
#620=CARTESIAN_POINT('',(1.20841666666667,0.,-4.08552980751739));
#621=CARTESIAN_POINT('',(1.19331770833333,0.,-4.12198191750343));
#622=CARTESIAN_POINT('',(1.16311979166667,0.,-4.19488613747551));
#623=CARTESIAN_POINT('',(1.14802083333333,0.,-4.23133824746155));
#624=CARTESIAN_POINT('',(1.11782291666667,0.,-4.30424246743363));
#625=CARTESIAN_POINT('',(1.10272395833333,0.,-4.34069457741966));
#626=CARTESIAN_POINT('',(1.07252604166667,0.,-4.41359879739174));
#627=CARTESIAN_POINT('',(1.05742708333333,0.,-4.45005090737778));
#628=CARTESIAN_POINT('',(1.02722916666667,0.,-4.52295512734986));
#629=CARTESIAN_POINT('',(1.01213020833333,0.,-4.5594072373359));
#630=CARTESIAN_POINT('',(0.981932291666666,0.,-4.63231145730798));
#631=CARTESIAN_POINT('',(0.966833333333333,0.,-4.66876356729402));
#632=CARTESIAN_POINT('',(0.936635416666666,0.,-4.7416677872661));
#633=CARTESIAN_POINT('',(0.921536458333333,0.,-4.77811989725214));
#634=CARTESIAN_POINT('',(0.891338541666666,0.,-4.85102411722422));
#635=CARTESIAN_POINT('',(0.876239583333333,0.,-4.88747622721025));
#636=CARTESIAN_POINT('',(0.846041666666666,0.,-4.96038044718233));
#637=CARTESIAN_POINT('',(0.830942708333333,0.,-4.99683255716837));
#638=CARTESIAN_POINT('',(0.800744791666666,0.,-5.06973677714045));
#639=CARTESIAN_POINT('',(0.785645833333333,0.,-5.10618888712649));
#640=CARTESIAN_POINT('',(0.755447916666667,0.,-5.17909310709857));
#641=CARTESIAN_POINT('',(0.740348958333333,0.,-5.21554521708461));
#642=CARTESIAN_POINT('',(0.710151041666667,0.,-5.28844943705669));
#643=CARTESIAN_POINT('',(0.695052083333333,0.,-5.32490154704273));
#644=CARTESIAN_POINT('',(0.664854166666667,0.,-5.39780576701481));
#645=CARTESIAN_POINT('',(0.649755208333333,0.,-5.43425787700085));
#646=CARTESIAN_POINT('',(0.619557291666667,0.,-5.50716209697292));
#647=CARTESIAN_POINT('',(0.604458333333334,0.,-5.54361420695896));
#648=CARTESIAN_POINT('',(0.574260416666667,0.,-5.61651842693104));
#649=CARTESIAN_POINT('',(0.559161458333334,0.,-5.65297053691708));
#650=CARTESIAN_POINT('',(0.528963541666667,0.,-5.72587475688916));
#651=CARTESIAN_POINT('',(0.513864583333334,0.,-5.7623268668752));
#652=CARTESIAN_POINT('',(0.483666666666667,0.,-5.83523108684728));
#653=CARTESIAN_POINT('',(0.468567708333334,0.,-5.87168319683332));
#654=CARTESIAN_POINT('',(0.438369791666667,0.,-5.9445874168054));
#655=CARTESIAN_POINT('',(0.423270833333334,0.,-5.98103952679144));
#656=CARTESIAN_POINT('',(0.393072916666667,0.,-6.05394374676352));
#657=CARTESIAN_POINT('',(0.377973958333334,0.,-6.09039585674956));
#658=CARTESIAN_POINT('',(0.347776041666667,0.,-6.16330007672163));
#659=CARTESIAN_POINT('',(0.332677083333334,0.,-6.19975218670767));
#660=CARTESIAN_POINT('',(0.302479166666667,0.,-6.27265640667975));
#661=CARTESIAN_POINT('',(0.287380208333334,0.,-6.30910851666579));
#662=CARTESIAN_POINT('',(0.257182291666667,0.,-6.38201273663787));
#663=CARTESIAN_POINT('',(0.242083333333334,0.,-6.41846484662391));
#664=CARTESIAN_POINT('',(0.211885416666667,0.,-6.49136906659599));
#665=CARTESIAN_POINT('',(0.196786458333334,0.,-6.52782117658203));
#666=CARTESIAN_POINT('',(0.166588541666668,0.,-6.60072539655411));
#667=CARTESIAN_POINT('',(0.151489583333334,0.,-6.63717750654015));
#668=CARTESIAN_POINT('',(0.121291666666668,0.,-6.71008172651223));
#669=CARTESIAN_POINT('',(0.106192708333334,0.,-6.74653383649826));
#670=CARTESIAN_POINT('',(0.0759947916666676,0.,-6.81943805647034));
#671=CARTESIAN_POINT('',(0.0608958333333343,0.,-6.85589016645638));
#672=CARTESIAN_POINT('',(0.0306979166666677,0.,-6.92879438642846));
#673=CARTESIAN_POINT('',(0.0155989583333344,0.,-6.9652464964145));
#674=CARTESIAN_POINT('',(0.000500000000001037,0.,-7.00169860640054));
#675=B_SPLINE_CURVE_WITH_KNOTS('',3,(#609,#610,#611,#612,#613,#614,#615,#616,#617,#618,#619,
#620,#621,#622,#623,#624,#625,#626,#627,#628,#629,#630,#631,#632,#633,#634,#635,#636,#637,#638,
#639,#640,#641,#642,#643,#644,#645,#646,#647,#648,#649,#650,#651,#652,#653,#654,#655,#656,#657,
#658,#659,#660,#661,#662,#663,#664,#665,#666,#667,#668,#669,#670,#671,#672,#673,#674),
.UNSPECIFIED.,.F.,.F.,(4,2,2,2,2,2,2,2,2,2,2,2,2,2,2,2,2,2,2,2,2,2,2,2,2,2,2,2,2,2,2,2,4),(0.,
0.118366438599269,0.236732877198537,0.355099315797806,0.473465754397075,0.591832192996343,
0.710198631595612,0.828565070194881,0.94693150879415,1.06529794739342,1.18366438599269,
1.30203082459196,1.42039726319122,1.53876370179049,1.65713014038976,1.77549657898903,
1.8938630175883,2.01222945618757,2.13059589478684,2.24896233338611,2.36732877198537,
2.48569521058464,2.60406164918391,2.72242808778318,2.84079452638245,2.95916096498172,
3.07752740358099,3.19589384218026,3.31426028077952,3.43262671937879,3.55099315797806,
3.66935959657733,3.7877260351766),.UNSPECIFIED.);
#676=EDGE_CURVE('BSEAM313',#590,#607,#675,.T.);
#677=ORIENTED_EDGE('',*,*,#591,.T.);
#678=ORIENTED_EDGE('',*,*,#608,.F.);
#679=ORIENTED_EDGE('',*,*,#676,.T.);
#680=ORIENTED_EDGE('',*,*,#676,.F.);
#681=EDGE_LOOP('',(#677,#679,#678,#680));
#682=FACE_BOUND('',#681,.T.);
#683=ADVANCED_FACE('F313',(#682),#600,.T.);
#684=CARTESIAN_POINT('',(0.,0.000500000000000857,-7.00169860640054));
#685=DIRECTION('',(0.,0.,-1.));
#686=DIRECTION('',(-1.,0.,0.));
#687=AXIS2_PLACEMENT_3D('',#684,#685,#686);
#688=PLANE('',#687);
#689=ORIENTED_EDGE('',*,*,#608,.T.);
#690=EDGE_LOOP('',(#689));
#691=FACE_BOUND('',#690,.T.);
#692=ADVANCED_FACE('F309',(#691),#688,.T.);
#693=CARTESIAN_POINT('',(0.,0.,0.));
#694=DIRECTION('',(0.,0.,1.));
#695=DIRECTION('',(1.,0.,0.));
#696=AXIS2_PLACEMENT_3D('',#693,#694,#695);
#697=PLANE('',#696);
#698=CARTESIAN_POINT('',(0.,1.12,0.));
#699=DIRECTION('',(0.,0.,1.));
#700=DIRECTION('',(1.,0.,0.));
#701=AXIS2_PLACEMENT_3D('',#698,#699,#700);
#702=CIRCLE('',#701,0.28);
#703=CARTESIAN_POINT('',(-0.272443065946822,1.18461250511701,0.));
#704=VERTEX_POINT('',#703);
#705=EDGE_CURVE('E358',#476,#704,#702,.T.);
#706=ORIENTED_EDGE('',*,*,#705,.F.);
#707=ORIENTED_EDGE('',*,*,#477,.F.);
#708=CARTESIAN_POINT('',(-0.969948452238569,0.560000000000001,0.));
#709=DIRECTION('',(0.,0.,1.));
#710=DIRECTION('',(1.,0.,0.));
#711=AXIS2_PLACEMENT_3D('',#708,#709,#710);
#712=CIRCLE('',#711,0.28);
#713=CARTESIAN_POINT('',(-0.889682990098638,0.828248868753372,0.));
#714=VERTEX_POINT('',#713);
#715=EDGE_CURVE('E355',#714,#474,#712,.T.);
#716=ORIENTED_EDGE('',*,*,#715,.F.);
#717=CARTESIAN_POINT('',(-0.749218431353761,1.29768438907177,0.));
#718=DIRECTION('',(0.,0.,1.));
#719=DIRECTION('',(1.,0.,0.));
#720=AXIS2_PLACEMENT_3D('',#717,#718,#719);
#721=CIRCLE('',#720,0.49);
#722=EDGE_CURVE('E350',#714,#704,#721,.T.);
#723=ORIENTED_EDGE('',*,*,#722,.T.);
#724=EDGE_LOOP('',(#706,#707,#716,#723));
#725=FACE_BOUND('',#724,.T.);
#726=ADVANCED_FACE('F312',(#725),#697,.T.);
#727=CARTESIAN_POINT('',(-0.969948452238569,0.560000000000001,-7.00269860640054));
#728=DIRECTION('',(0.,0.,1.));
#729=DIRECTION('',(1.,0.,0.));
#730=AXIS2_PLACEMENT_3D('',#727,#728,#729);
#731=CYLINDRICAL_SURFACE('',#730,0.28);
#732=ORIENTED_EDGE('',*,*,#69,.F.);
#733=DIRECTION('',(0.,0.,1.));
#734=VECTOR('',#733,1.);
#735=CARTESIAN_POINT('',(-0.889682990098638,0.828248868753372,-7.00269860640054));
#736=LINE('',#735,#734);
#737=EDGE_CURVE('E347',#66,#714,#736,.T.);
#738=ORIENTED_EDGE('',*,*,#737,.T.);
#739=ORIENTED_EDGE('',*,*,#715,.T.);
#740=CARTESIAN_POINT('',(-0.96994845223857,0.559999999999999,0.));
#741=DIRECTION('',(0.,0.,1.));
#742=DIRECTION('',(1.,0.,0.));
#743=AXIS2_PLACEMENT_3D('',#740,#741,#742);
#744=CIRCLE('',#743,0.28);
#745=CARTESIAN_POINT('',(-1.16212605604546,0.356363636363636,0.));
#746=VERTEX_POINT('',#745);
#747=EDGE_CURVE('E257',#474,#746,#744,.T.);
#748=ORIENTED_EDGE('',*,*,#747,.T.);
#749=DIRECTION('',(0.,0.,1.));
#750=VECTOR('',#749,1.);
#751=CARTESIAN_POINT('',(-1.16212605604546,0.356363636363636,-7.00269860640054));
#752=LINE('',#751,#750);
#753=EDGE_CURVE('E269',#68,#746,#752,.T.);
#754=ORIENTED_EDGE('',*,*,#753,.F.);
#755=EDGE_LOOP('',(#732,#738,#739,#748,#754));
#756=FACE_BOUND('',#755,.T.);
#757=ADVANCED_FACE('F393',(#756),#731,.F.);
#758=CARTESIAN_POINT('',(-0.749218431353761,1.29768438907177,-7.00269860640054));
#759=DIRECTION('',(0.,0.,1.));
#760=DIRECTION('',(1.,0.,0.));
#761=AXIS2_PLACEMENT_3D('',#758,#759,#760);
#762=CYLINDRICAL_SURFACE('',#761,0.49);
#763=ORIENTED_EDGE('',*,*,#737,.F.);
#764=ORIENTED_EDGE('',*,*,#458,.T.);
#765=DIRECTION('',(0.,0.,1.));
#766=VECTOR('',#765,1.);
#767=CARTESIAN_POINT('',(-0.272443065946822,1.18461250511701,-7.00269860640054));
#768=LINE('',#767,#766);
#769=EDGE_CURVE('E349',#428,#704,#768,.T.);
#770=ORIENTED_EDGE('',*,*,#769,.T.);
#771=ORIENTED_EDGE('',*,*,#722,.F.);
#772=EDGE_LOOP('',(#763,#764,#770,#771));
#773=FACE_BOUND('',#772,.T.);
#774=ADVANCED_FACE('F396',(#773),#762,.T.);
#775=CARTESIAN_POINT('',(0.,1.12,-7.00269860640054));
#776=DIRECTION('',(0.,0.,1.));
#777=DIRECTION('',(1.,0.,0.));
#778=AXIS2_PLACEMENT_3D('',#775,#776,#777);
#779=CYLINDRICAL_SURFACE('',#778,0.28);
#780=ORIENTED_EDGE('',*,*,#429,.F.);
#781=DIRECTION('',(0.,0.,1.));
#782=VECTOR('',#781,1.);
#783=CARTESIAN_POINT('',(0.272443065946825,1.18461250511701,-7.00269860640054));
#784=LINE('',#783,#782);
#785=CARTESIAN_POINT('',(0.272443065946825,1.18461250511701,0.));
#786=VERTEX_POINT('',#785);
#787=EDGE_CURVE('E518',#387,#786,#784,.T.);
#788=ORIENTED_EDGE('',*,*,#787,.T.);
#789=CARTESIAN_POINT('',(0.,1.12,0.));
#790=DIRECTION('',(0.,0.,1.));
#791=DIRECTION('',(1.,0.,0.));
#792=AXIS2_PLACEMENT_3D('',#789,#790,#791);
#793=CIRCLE('',#792,0.28);
#794=EDGE_CURVE('E516',#786,#476,#793,.T.);
#795=ORIENTED_EDGE('',*,*,#794,.T.);
#796=ORIENTED_EDGE('',*,*,#705,.T.);
#797=ORIENTED_EDGE('',*,*,#769,.F.);
#798=EDGE_LOOP('',(#780,#788,#795,#796,#797));
#799=FACE_BOUND('',#798,.T.);
#800=ADVANCED_FACE('F306',(#799),#779,.F.);
#801=CARTESIAN_POINT('',(0.,0.,0.));
#802=DIRECTION('',(0.,0.,1.));
#803=DIRECTION('',(1.,0.,0.));
#804=AXIS2_PLACEMENT_3D('',#801,#802,#803);
#805=PLANE('',#804);
#806=CARTESIAN_POINT('',(0.969948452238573,0.560000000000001,0.));
#807=DIRECTION('',(0.,0.,1.));
#808=DIRECTION('',(1.,0.,0.));
#809=AXIS2_PLACEMENT_3D('',#806,#807,#808);
#810=CIRCLE('',#809,0.28);
#811=CARTESIAN_POINT('',(0.889682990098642,0.828248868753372,0.));
#812=VERTEX_POINT('',#811);
#813=EDGE_CURVE('E510',#485,#812,#810,.T.);
#814=ORIENTED_EDGE('',*,*,#813,.F.);
#815=ORIENTED_EDGE('',*,*,#486,.T.);
#816=ORIENTED_EDGE('',*,*,#794,.F.);
#817=CARTESIAN_POINT('',(0.749218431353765,1.29768438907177,0.));
#818=DIRECTION('',(0.,0.,1.));
#819=DIRECTION('',(1.,0.,0.));
#820=AXIS2_PLACEMENT_3D('',#817,#818,#819);
#821=CIRCLE('',#820,0.49);
#822=EDGE_CURVE('E515',#786,#812,#821,.T.);
#823=ORIENTED_EDGE('',*,*,#822,.T.);
#824=EDGE_LOOP('',(#814,#815,#816,#823));
#825=FACE_BOUND('',#824,.T.);
#826=ADVANCED_FACE('F404',(#825),#805,.T.);
#827=CARTESIAN_POINT('',(0.749218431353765,1.29768438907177,-7.00269860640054));
#828=DIRECTION('',(0.,0.,1.));
#829=DIRECTION('',(1.,0.,0.));
#830=AXIS2_PLACEMENT_3D('',#827,#828,#829);
#831=CYLINDRICAL_SURFACE('',#830,0.49);
#832=ORIENTED_EDGE('',*,*,#787,.F.);
#833=ORIENTED_EDGE('',*,*,#388,.T.);
#834=DIRECTION('',(0.,0.,1.));
#835=VECTOR('',#834,1.);
#836=CARTESIAN_POINT('',(0.889682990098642,0.828248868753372,-7.00269860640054));
#837=LINE('',#836,#835);
#838=EDGE_CURVE('E513',#356,#812,#837,.T.);
#839=ORIENTED_EDGE('',*,*,#838,.T.);
#840=ORIENTED_EDGE('',*,*,#822,.F.);
#841=EDGE_LOOP('',(#832,#833,#839,#840));
#842=FACE_BOUND('',#841,.T.);
#843=ADVANCED_FACE('F501',(#842),#831,.T.);
#844=CARTESIAN_POINT('',(0.969948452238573,0.560000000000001,-7.00269860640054));
#845=DIRECTION('',(0.,0.,1.));
#846=DIRECTION('',(1.,0.,0.));
#847=AXIS2_PLACEMENT_3D('',#844,#845,#846);
#848=CYLINDRICAL_SURFACE('',#847,0.28);
#849=ORIENTED_EDGE('',*,*,#357,.F.);
#850=DIRECTION('',(0.,0.,1.));
#851=VECTOR('',#850,1.);
#852=CARTESIAN_POINT('',(1.16212605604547,0.356363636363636,-7.00269860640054));
#853=LINE('',#852,#851);
#854=CARTESIAN_POINT('',(1.16212605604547,0.356363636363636,0.));
#855=VERTEX_POINT('',#854);
#856=EDGE_CURVE('E694',#315,#855,#853,.T.);
#857=ORIENTED_EDGE('',*,*,#856,.T.);
#858=CARTESIAN_POINT('',(0.969948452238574,0.559999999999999,0.));
#859=DIRECTION('',(0.,0.,1.));
#860=DIRECTION('',(1.,0.,0.));
#861=AXIS2_PLACEMENT_3D('',#858,#859,#860);
#862=CIRCLE('',#861,0.28);
#863=EDGE_CURVE('E529',#855,#485,#862,.T.);
#864=ORIENTED_EDGE('',*,*,#863,.T.);
#865=ORIENTED_EDGE('',*,*,#813,.T.);
#866=ORIENTED_EDGE('',*,*,#838,.F.);
#867=EDGE_LOOP('',(#849,#857,#864,#865,#866));
#868=FACE_BOUND('',#867,.T.);
#869=ADVANCED_FACE('F497',(#868),#848,.F.);
#870=CARTESIAN_POINT('',(0.,0.,0.));
#871=DIRECTION('',(0.,0.,1.));
#872=DIRECTION('',(1.,0.,0.));
#873=AXIS2_PLACEMENT_3D('',#870,#871,#872);
#874=PLANE('',#873);
#875=CARTESIAN_POINT('',(0.969948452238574,-0.559999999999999,0.));
#876=DIRECTION('',(0.,0.,1.));
#877=DIRECTION('',(1.,0.,0.));
#878=AXIS2_PLACEMENT_3D('',#875,#876,#877);
#879=CIRCLE('',#878,0.28);
#880=CARTESIAN_POINT('',(1.16212605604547,-0.356363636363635,0.));
#881=VERTEX_POINT('',#880);
#882=EDGE_CURVE('E486',#494,#881,#879,.T.);
#883=ORIENTED_EDGE('',*,*,#882,.F.);
#884=ORIENTED_EDGE('',*,*,#495,.T.);
#885=ORIENTED_EDGE('',*,*,#863,.F.);
#886=CARTESIAN_POINT('',(1.49843686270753,0.,0.));
#887=DIRECTION('',(0.,0.,1.));
#888=DIRECTION('',(1.,0.,0.));
#889=AXIS2_PLACEMENT_3D('',#886,#887,#888);
#890=CIRCLE('',#889,0.49);
#891=EDGE_CURVE('E689',#855,#881,#890,.T.);
#892=ORIENTED_EDGE('',*,*,#891,.T.);
#893=EDGE_LOOP('',(#883,#884,#885,#892));
#894=FACE_BOUND('',#893,.T.);
#895=ADVANCED_FACE('F496',(#894),#874,.T.);
#896=CARTESIAN_POINT('',(1.49843686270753,0.,-7.00269860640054));
#897=DIRECTION('',(0.,0.,1.));
#898=DIRECTION('',(1.,0.,0.));
#899=AXIS2_PLACEMENT_3D('',#896,#897,#898);
#900=CYLINDRICAL_SURFACE('',#899,0.49);
#901=ORIENTED_EDGE('',*,*,#856,.F.);
#902=ORIENTED_EDGE('',*,*,#316,.T.);
#903=DIRECTION('',(0.,0.,1.));
#904=VECTOR('',#903,1.);
#905=CARTESIAN_POINT('',(1.16212605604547,-0.356363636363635,-7.00269860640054));
#906=LINE('',#905,#904);
#907=EDGE_CURVE('E690',#284,#881,#906,.T.);
#908=ORIENTED_EDGE('',*,*,#907,.T.);
#909=ORIENTED_EDGE('',*,*,#891,.F.);
#910=EDGE_LOOP('',(#901,#902,#908,#909));
#911=FACE_BOUND('',#910,.T.);
#912=ADVANCED_FACE('F472',(#911),#900,.T.);
#913=CARTESIAN_POINT('',(0.969948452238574,-0.559999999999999,-7.00269860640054));
#914=DIRECTION('',(0.,0.,1.));
#915=DIRECTION('',(1.,0.,0.));
#916=AXIS2_PLACEMENT_3D('',#913,#914,#915);
#917=CYLINDRICAL_SURFACE('',#916,0.28);
#918=ORIENTED_EDGE('',*,*,#285,.F.);
#919=DIRECTION('',(0.,0.,1.));
#920=VECTOR('',#919,1.);
#921=CARTESIAN_POINT('',(0.889682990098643,-0.828248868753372,-7.00269860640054));
#922=LINE('',#921,#920);
#923=CARTESIAN_POINT('',(0.889682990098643,-0.828248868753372,0.));
#924=VERTEX_POINT('',#923);
#925=EDGE_CURVE('E686',#243,#924,#922,.T.);
#926=ORIENTED_EDGE('',*,*,#925,.T.);
#927=CARTESIAN_POINT('',(0.969948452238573,-0.56,0.));
#928=DIRECTION('',(0.,0.,1.));
#929=DIRECTION('',(1.,0.,0.));
#930=AXIS2_PLACEMENT_3D('',#927,#928,#929);
#931=CIRCLE('',#930,0.28);
#932=EDGE_CURVE('E679',#924,#494,#931,.T.);
#933=ORIENTED_EDGE('',*,*,#932,.T.);
#934=ORIENTED_EDGE('',*,*,#882,.T.);
#935=ORIENTED_EDGE('',*,*,#907,.F.);
#936=EDGE_LOOP('',(#918,#926,#933,#934,#935));
#937=FACE_BOUND('',#936,.T.);
#938=ADVANCED_FACE('F467',(#937),#917,.F.);
#939=CARTESIAN_POINT('',(0.,0.,0.));
#940=DIRECTION('',(0.,0.,1.));
#941=DIRECTION('',(1.,0.,0.));
#942=AXIS2_PLACEMENT_3D('',#939,#940,#941);
#943=PLANE('',#942);
#944=CARTESIAN_POINT('',(0.,-1.12,0.));
#945=DIRECTION('',(0.,0.,1.));
#946=DIRECTION('',(1.,0.,0.));
#947=AXIS2_PLACEMENT_3D('',#944,#945,#946);
#948=CIRCLE('',#947,0.28);
#949=CARTESIAN_POINT('',(0.272443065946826,-1.18461250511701,0.));
#950=VERTEX_POINT('',#949);
#951=EDGE_CURVE('E457',#503,#950,#948,.T.);
#952=ORIENTED_EDGE('',*,*,#951,.F.);
#953=ORIENTED_EDGE('',*,*,#504,.T.);
#954=ORIENTED_EDGE('',*,*,#932,.F.);
#955=CARTESIAN_POINT('',(0.749218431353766,-1.29768438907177,0.));
#956=DIRECTION('',(0.,0.,1.));
#957=DIRECTION('',(1.,0.,0.));
#958=AXIS2_PLACEMENT_3D('',#955,#956,#957);
#959=CIRCLE('',#958,0.49);
#960=EDGE_CURVE('E416',#924,#950,#959,.T.);
#961=ORIENTED_EDGE('',*,*,#960,.T.);
#962=EDGE_LOOP('',(#952,#953,#954,#961));
#963=FACE_BOUND('',#962,.T.);
#964=ADVANCED_FACE('F466',(#963),#943,.T.);
#965=CARTESIAN_POINT('',(0.749218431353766,-1.29768438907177,-7.00269860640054));
#966=DIRECTION('',(0.,0.,1.));
#967=DIRECTION('',(1.,0.,0.));
#968=AXIS2_PLACEMENT_3D('',#965,#966,#967);
#969=CYLINDRICAL_SURFACE('',#968,0.49);
#970=ORIENTED_EDGE('',*,*,#925,.F.);
#971=ORIENTED_EDGE('',*,*,#244,.T.);
#972=DIRECTION('',(0.,0.,1.));
#973=VECTOR('',#972,1.);
#974=CARTESIAN_POINT('',(0.272443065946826,-1.18461250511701,-7.00269860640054));
#975=LINE('',#974,#973);
#976=EDGE_CURVE('E702',#212,#950,#975,.T.);
#977=ORIENTED_EDGE('',*,*,#976,.T.);
#978=ORIENTED_EDGE('',*,*,#960,.F.);
#979=EDGE_LOOP('',(#970,#971,#977,#978));
#980=FACE_BOUND('',#979,.T.);
#981=ADVANCED_FACE('F443',(#980),#969,.T.);
#982=CARTESIAN_POINT('',(0.,-1.12,-7.00269860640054));
#983=DIRECTION('',(0.,0.,1.));
#984=DIRECTION('',(1.,0.,0.));
#985=AXIS2_PLACEMENT_3D('',#982,#983,#984);
#986=CYLINDRICAL_SURFACE('',#985,0.28);
#987=ORIENTED_EDGE('',*,*,#213,.F.);
#988=DIRECTION('',(0.,0.,1.));
#989=VECTOR('',#988,1.);
#990=CARTESIAN_POINT('',(-0.27244306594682,-1.18461250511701,-7.00269860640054));
#991=LINE('',#990,#989);
#992=CARTESIAN_POINT('',(-0.27244306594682,-1.18461250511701,0.));
#993=VERTEX_POINT('',#992);
#994=EDGE_CURVE('E284',#171,#993,#991,.T.);
#995=ORIENTED_EDGE('',*,*,#994,.T.);
#996=CARTESIAN_POINT('',(0.,-1.12,0.));
#997=DIRECTION('',(0.,0.,1.));
#998=DIRECTION('',(1.,0.,0.));
#999=AXIS2_PLACEMENT_3D('',#996,#997,#998);
#1000=CIRCLE('',#999,0.28);
#1001=EDGE_CURVE('E672',#993,#503,#1000,.T.);
#1002=ORIENTED_EDGE('',*,*,#1001,.T.);
#1003=ORIENTED_EDGE('',*,*,#951,.T.);
#1004=ORIENTED_EDGE('',*,*,#976,.F.);
#1005=EDGE_LOOP('',(#987,#995,#1002,#1003,#1004));
#1006=FACE_BOUND('',#1005,.T.);
#1007=ADVANCED_FACE('F438',(#1006),#986,.F.);
#1008=CARTESIAN_POINT('',(0.,0.,0.));
#1009=DIRECTION('',(0.,0.,1.));
#1010=DIRECTION('',(1.,0.,0.));
#1011=AXIS2_PLACEMENT_3D('',#1008,#1009,#1010);
#1012=PLANE('',#1011);
#1013=CARTESIAN_POINT('',(-0.969948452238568,-0.560000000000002,0.));
#1014=DIRECTION('',(0.,0.,1.));
#1015=DIRECTION('',(1.,0.,0.));
#1016=AXIS2_PLACEMENT_3D('',#1013,#1014,#1015);
#1017=CIRCLE('',#1016,0.28);
#1018=CARTESIAN_POINT('',(-0.889682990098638,-0.828248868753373,0.));
#1019=VERTEX_POINT('',#1018);
#1020=EDGE_CURVE('E414',#512,#1019,#1017,.T.);
#1021=ORIENTED_EDGE('',*,*,#1020,.F.);
#1022=ORIENTED_EDGE('',*,*,#513,.T.);
#1023=ORIENTED_EDGE('',*,*,#1001,.F.);
#1024=CARTESIAN_POINT('',(-0.749218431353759,-1.29768438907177,0.));
#1025=DIRECTION('',(0.,0.,1.));
#1026=DIRECTION('',(1.,0.,0.));
#1027=AXIS2_PLACEMENT_3D('',#1024,#1025,#1026);
#1028=CIRCLE('',#1027,0.49);
#1029=EDGE_CURVE('E669',#993,#1019,#1028,.T.);
#1030=ORIENTED_EDGE('',*,*,#1029,.T.);
#1031=EDGE_LOOP('',(#1021,#1022,#1023,#1030));
#1032=FACE_BOUND('',#1031,.T.);
#1033=ADVANCED_FACE('F437',(#1032),#1012,.T.);
#1034=CARTESIAN_POINT('',(-0.749218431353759,-1.29768438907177,-7.00269860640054));
#1035=DIRECTION('',(0.,0.,1.));
#1036=DIRECTION('',(1.,0.,0.));
#1037=AXIS2_PLACEMENT_3D('',#1034,#1035,#1036);
#1038=CYLINDRICAL_SURFACE('',#1037,0.49);
#1039=ORIENTED_EDGE('',*,*,#994,.F.);
#1040=ORIENTED_EDGE('',*,*,#172,.T.);
#1041=DIRECTION('',(0.,0.,1.));
#1042=VECTOR('',#1041,1.);
#1043=CARTESIAN_POINT('',(-0.889682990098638,-0.828248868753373,-7.00269860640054));
#1044=LINE('',#1043,#1042);
#1045=EDGE_CURVE('E418',#140,#1019,#1044,.T.);
#1046=ORIENTED_EDGE('',*,*,#1045,.T.);
#1047=ORIENTED_EDGE('',*,*,#1029,.F.);
#1048=EDGE_LOOP('',(#1039,#1040,#1046,#1047));
#1049=FACE_BOUND('',#1048,.T.);
#1050=ADVANCED_FACE('F295',(#1049),#1038,.T.);
#1051=CARTESIAN_POINT('',(-0.969948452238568,-0.560000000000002,-7.00269860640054));
#1052=DIRECTION('',(0.,0.,1.));
#1053=DIRECTION('',(1.,0.,0.));
#1054=AXIS2_PLACEMENT_3D('',#1051,#1052,#1053);
#1055=CYLINDRICAL_SURFACE('',#1054,0.28);
#1056=ORIENTED_EDGE('',*,*,#141,.F.);
#1057=DIRECTION('',(0.,0.,1.));
#1058=VECTOR('',#1057,1.);
#1059=CARTESIAN_POINT('',(-1.16212605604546,-0.356363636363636,-7.00269860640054));
#1060=LINE('',#1059,#1058);
#1061=CARTESIAN_POINT('',(-1.16212605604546,-0.356363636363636,0.));
#1062=VERTEX_POINT('',#1061);
#1063=EDGE_CURVE('E245',#99,#1062,#1060,.T.);
#1064=ORIENTED_EDGE('',*,*,#1063,.T.);
#1065=CARTESIAN_POINT('',(-0.96994845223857,-0.559999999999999,0.));
#1066=DIRECTION('',(0.,0.,1.));
#1067=DIRECTION('',(1.,0.,0.));
#1068=AXIS2_PLACEMENT_3D('',#1065,#1066,#1067);
#1069=CIRCLE('',#1068,0.28);
#1070=EDGE_CURVE('E249',#1062,#512,#1069,.T.);
#1071=ORIENTED_EDGE('',*,*,#1070,.T.);
#1072=ORIENTED_EDGE('',*,*,#1020,.T.);
#1073=ORIENTED_EDGE('',*,*,#1045,.F.);
#1074=EDGE_LOOP('',(#1056,#1064,#1071,#1072,#1073));
#1075=FACE_BOUND('',#1074,.T.);
#1076=ADVANCED_FACE('F247',(#1075),#1055,.F.);
#1077=CARTESIAN_POINT('',(0.,0.,0.));
#1078=DIRECTION('',(0.,0.,1.));
#1079=DIRECTION('',(1.,0.,0.));
#1080=AXIS2_PLACEMENT_3D('',#1077,#1078,#1079);
#1081=PLANE('',#1080);
#1082=ORIENTED_EDGE('',*,*,#1070,.F.);
#1083=CARTESIAN_POINT('',(-1.49843686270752,0.,0.));
#1084=DIRECTION('',(0.,0.,1.));
#1085=DIRECTION('',(1.,0.,0.));
#1086=AXIS2_PLACEMENT_3D('',#1083,#1084,#1085);
#1087=CIRCLE('',#1086,0.49);
#1088=EDGE_CURVE('E262',#1062,#746,#1087,.T.);
#1089=ORIENTED_EDGE('',*,*,#1088,.T.);
#1090=ORIENTED_EDGE('',*,*,#747,.F.);
#1091=ORIENTED_EDGE('',*,*,#520,.T.);
#1092=EDGE_LOOP('',(#1082,#1089,#1090,#1091));
#1093=FACE_BOUND('',#1092,.T.);
#1094=ADVANCED_FACE('F261',(#1093),#1081,.T.);
#1095=CARTESIAN_POINT('',(-1.49843686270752,0.,-7.00269860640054));
#1096=DIRECTION('',(0.,0.,1.));
#1097=DIRECTION('',(1.,0.,0.));
#1098=AXIS2_PLACEMENT_3D('',#1095,#1096,#1097);
#1099=CYLINDRICAL_SURFACE('',#1098,0.49);
#1100=ORIENTED_EDGE('',*,*,#1063,.F.);
#1101=ORIENTED_EDGE('',*,*,#100,.T.);
#1102=ORIENTED_EDGE('',*,*,#753,.T.);
#1103=ORIENTED_EDGE('',*,*,#1088,.F.);
#1104=EDGE_LOOP('',(#1100,#1101,#1102,#1103));
#1105=FACE_BOUND('',#1104,.T.);
#1106=ADVANCED_FACE('F267',(#1105),#1099,.T.);
#1107=CLOSED_SHELL('',(#462,#535,#555,#575,#595,#683,#692,#726,#757,#774,#800,#826,#843,#869,
#895,#912,#938,#964,#981,#1007,#1033,#1050,#1076,#1094,#1106));
#1108=MANIFOLD_SOLID_BREP('B2',#1107);
#1109=ADVANCED_BREP_SHAPE_REPRESENTATION('',(#18,#1108),#14);
#1110=SHAPE_DEFINITION_REPRESENTATION(#9,#1109);
ENDSEC;
END-ISO-10303-21;
